VERSION 5.8 ;
BUSBITCHARS "[]" ;
DIVIDERCHAR "/" ;
UNITS
    DATABASE MICRONS 1000 ;
END UNITS

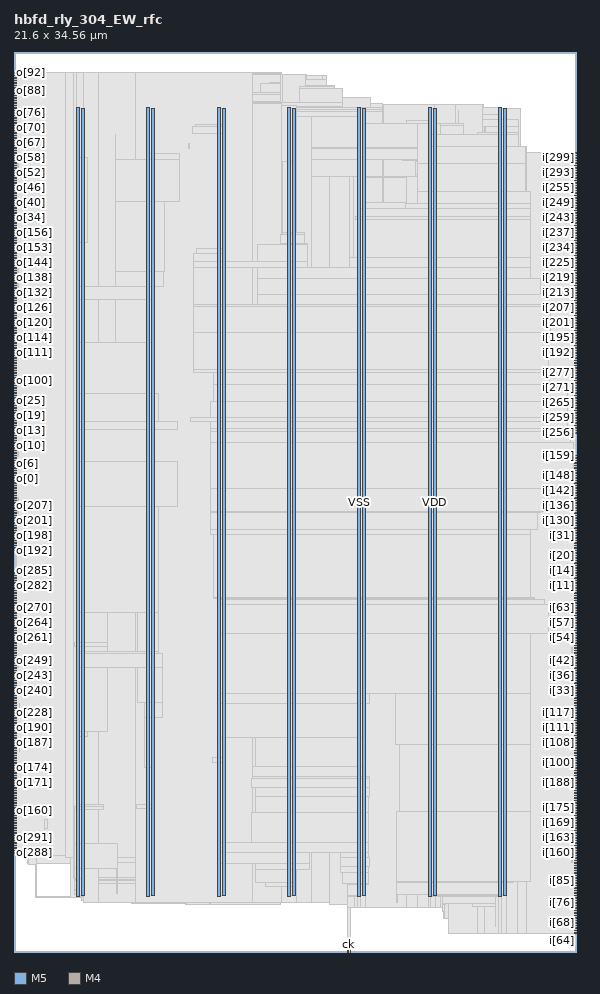
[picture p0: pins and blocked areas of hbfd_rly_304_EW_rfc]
MACRO hbfd_rly_304_EW_rfc
  FOREIGN hbfd_rly_304_EW_rfc 0 0 ;
  CLASS BLOCK ;
  SIZE 21.6 BY 34.56 ;
  PIN ck
    DIRECTION INPUT ;
    USE SIGNAL ;
    PORT
      LAYER M5 ;
        RECT  12.816 0 12.84 0.084 ;
    END
  END ck
  PIN i[0]
    DIRECTION INPUT ;
    USE SIGNAL ;
    PORT
      LAYER M4 ;
        RECT  21.516 13.008 21.6 13.032 ;
    END
  END i[0]
  PIN i[100]
    DIRECTION INPUT ;
    USE SIGNAL ;
    PORT
      LAYER M4 ;
        RECT  21.516 7.248 21.6 7.272 ;
    END
  END i[100]
  PIN i[101]
    DIRECTION INPUT ;
    USE SIGNAL ;
    PORT
      LAYER M4 ;
        RECT  21.516 7.344 21.6 7.368 ;
    END
  END i[101]
  PIN i[102]
    DIRECTION INPUT ;
    USE SIGNAL ;
    PORT
      LAYER M4 ;
        RECT  21.516 7.44 21.6 7.464 ;
    END
  END i[102]
  PIN i[103]
    DIRECTION INPUT ;
    USE SIGNAL ;
    PORT
      LAYER M4 ;
        RECT  21.516 7.536 21.6 7.56 ;
    END
  END i[103]
  PIN i[104]
    DIRECTION INPUT ;
    USE SIGNAL ;
    PORT
      LAYER M4 ;
        RECT  21.516 7.632 21.6 7.656 ;
    END
  END i[104]
  PIN i[105]
    DIRECTION INPUT ;
    USE SIGNAL ;
    PORT
      LAYER M4 ;
        RECT  21.516 7.728 21.6 7.752 ;
    END
  END i[105]
  PIN i[106]
    DIRECTION INPUT ;
    USE SIGNAL ;
    PORT
      LAYER M4 ;
        RECT  21.516 7.824 21.6 7.848 ;
    END
  END i[106]
  PIN i[107]
    DIRECTION INPUT ;
    USE SIGNAL ;
    PORT
      LAYER M4 ;
        RECT  21.516 7.92 21.6 7.944 ;
    END
  END i[107]
  PIN i[108]
    DIRECTION INPUT ;
    USE SIGNAL ;
    PORT
      LAYER M4 ;
        RECT  21.516 8.016 21.6 8.04 ;
    END
  END i[108]
  PIN i[109]
    DIRECTION INPUT ;
    USE SIGNAL ;
    PORT
      LAYER M4 ;
        RECT  21.516 8.112 21.6 8.136 ;
    END
  END i[109]
  PIN i[10]
    DIRECTION INPUT ;
    USE SIGNAL ;
    PORT
      LAYER M4 ;
        RECT  21.516 13.968 21.6 13.992 ;
    END
  END i[10]
  PIN i[110]
    DIRECTION INPUT ;
    USE SIGNAL ;
    PORT
      LAYER M4 ;
        RECT  21.516 8.208 21.6 8.232 ;
    END
  END i[110]
  PIN i[111]
    DIRECTION INPUT ;
    USE SIGNAL ;
    PORT
      LAYER M4 ;
        RECT  21.516 8.304 21.6 8.328 ;
    END
  END i[111]
  PIN i[112]
    DIRECTION INPUT ;
    USE SIGNAL ;
    PORT
      LAYER M4 ;
        RECT  21.516 8.4 21.6 8.424 ;
    END
  END i[112]
  PIN i[113]
    DIRECTION INPUT ;
    USE SIGNAL ;
    PORT
      LAYER M4 ;
        RECT  21.516 8.496 21.6 8.52 ;
    END
  END i[113]
  PIN i[114]
    DIRECTION INPUT ;
    USE SIGNAL ;
    PORT
      LAYER M4 ;
        RECT  21.516 8.592 21.6 8.616 ;
    END
  END i[114]
  PIN i[115]
    DIRECTION INPUT ;
    USE SIGNAL ;
    PORT
      LAYER M4 ;
        RECT  21.516 8.688 21.6 8.712 ;
    END
  END i[115]
  PIN i[116]
    DIRECTION INPUT ;
    USE SIGNAL ;
    PORT
      LAYER M4 ;
        RECT  21.516 8.784 21.6 8.808 ;
    END
  END i[116]
  PIN i[117]
    DIRECTION INPUT ;
    USE SIGNAL ;
    PORT
      LAYER M4 ;
        RECT  21.516 8.88 21.6 8.904 ;
    END
  END i[117]
  PIN i[118]
    DIRECTION INPUT ;
    USE SIGNAL ;
    PORT
      LAYER M4 ;
        RECT  21.516 8.976 21.6 9 ;
    END
  END i[118]
  PIN i[119]
    DIRECTION INPUT ;
    USE SIGNAL ;
    PORT
      LAYER M4 ;
        RECT  21.516 9.072 21.6 9.096 ;
    END
  END i[119]
  PIN i[11]
    DIRECTION INPUT ;
    USE SIGNAL ;
    PORT
      LAYER M4 ;
        RECT  21.516 14.064 21.6 14.088 ;
    END
  END i[11]
  PIN i[120]
    DIRECTION INPUT ;
    USE SIGNAL ;
    PORT
      LAYER M4 ;
        RECT  21.516 9.168 21.6 9.192 ;
    END
  END i[120]
  PIN i[121]
    DIRECTION INPUT ;
    USE SIGNAL ;
    PORT
      LAYER M4 ;
        RECT  21.516 9.264 21.6 9.288 ;
    END
  END i[121]
  PIN i[122]
    DIRECTION INPUT ;
    USE SIGNAL ;
    PORT
      LAYER M4 ;
        RECT  21.516 9.36 21.6 9.384 ;
    END
  END i[122]
  PIN i[123]
    DIRECTION INPUT ;
    USE SIGNAL ;
    PORT
      LAYER M4 ;
        RECT  21.516 9.456 21.6 9.48 ;
    END
  END i[123]
  PIN i[124]
    DIRECTION INPUT ;
    USE SIGNAL ;
    PORT
      LAYER M4 ;
        RECT  21.516 9.552 21.6 9.576 ;
    END
  END i[124]
  PIN i[125]
    DIRECTION INPUT ;
    USE SIGNAL ;
    PORT
      LAYER M4 ;
        RECT  21.516 9.648 21.6 9.672 ;
    END
  END i[125]
  PIN i[126]
    DIRECTION INPUT ;
    USE SIGNAL ;
    PORT
      LAYER M4 ;
        RECT  21.516 9.744 21.6 9.768 ;
    END
  END i[126]
  PIN i[127]
    DIRECTION INPUT ;
    USE SIGNAL ;
    PORT
      LAYER M4 ;
        RECT  21.516 9.84 21.6 9.864 ;
    END
  END i[127]
  PIN i[128]
    DIRECTION INPUT ;
    USE SIGNAL ;
    PORT
      LAYER M4 ;
        RECT  21.516 16.08 21.6 16.104 ;
    END
  END i[128]
  PIN i[129]
    DIRECTION INPUT ;
    USE SIGNAL ;
    PORT
      LAYER M4 ;
        RECT  21.516 16.176 21.6 16.2 ;
    END
  END i[129]
  PIN i[12]
    DIRECTION INPUT ;
    USE SIGNAL ;
    PORT
      LAYER M4 ;
        RECT  21.516 14.16 21.6 14.184 ;
    END
  END i[12]
  PIN i[130]
    DIRECTION INPUT ;
    USE SIGNAL ;
    PORT
      LAYER M4 ;
        RECT  21.516 16.272 21.6 16.296 ;
    END
  END i[130]
  PIN i[131]
    DIRECTION INPUT ;
    USE SIGNAL ;
    PORT
      LAYER M4 ;
        RECT  21.516 16.368 21.6 16.392 ;
    END
  END i[131]
  PIN i[132]
    DIRECTION INPUT ;
    USE SIGNAL ;
    PORT
      LAYER M4 ;
        RECT  21.516 16.464 21.6 16.488 ;
    END
  END i[132]
  PIN i[133]
    DIRECTION INPUT ;
    USE SIGNAL ;
    PORT
      LAYER M4 ;
        RECT  21.516 16.56 21.6 16.584 ;
    END
  END i[133]
  PIN i[134]
    DIRECTION INPUT ;
    USE SIGNAL ;
    PORT
      LAYER M4 ;
        RECT  21.516 16.656 21.6 16.68 ;
    END
  END i[134]
  PIN i[135]
    DIRECTION INPUT ;
    USE SIGNAL ;
    PORT
      LAYER M4 ;
        RECT  21.516 16.752 21.6 16.776 ;
    END
  END i[135]
  PIN i[136]
    DIRECTION INPUT ;
    USE SIGNAL ;
    PORT
      LAYER M4 ;
        RECT  21.516 16.848 21.6 16.872 ;
    END
  END i[136]
  PIN i[137]
    DIRECTION INPUT ;
    USE SIGNAL ;
    PORT
      LAYER M4 ;
        RECT  21.516 16.944 21.6 16.968 ;
    END
  END i[137]
  PIN i[138]
    DIRECTION INPUT ;
    USE SIGNAL ;
    PORT
      LAYER M4 ;
        RECT  21.516 17.04 21.6 17.064 ;
    END
  END i[138]
  PIN i[139]
    DIRECTION INPUT ;
    USE SIGNAL ;
    PORT
      LAYER M4 ;
        RECT  21.516 17.136 21.6 17.16 ;
    END
  END i[139]
  PIN i[13]
    DIRECTION INPUT ;
    USE SIGNAL ;
    PORT
      LAYER M4 ;
        RECT  21.516 14.256 21.6 14.28 ;
    END
  END i[13]
  PIN i[140]
    DIRECTION INPUT ;
    USE SIGNAL ;
    PORT
      LAYER M4 ;
        RECT  21.516 17.232 21.6 17.256 ;
    END
  END i[140]
  PIN i[141]
    DIRECTION INPUT ;
    USE SIGNAL ;
    PORT
      LAYER M4 ;
        RECT  21.516 17.328 21.6 17.352 ;
    END
  END i[141]
  PIN i[142]
    DIRECTION INPUT ;
    USE SIGNAL ;
    PORT
      LAYER M4 ;
        RECT  21.516 17.424 21.6 17.448 ;
    END
  END i[142]
  PIN i[143]
    DIRECTION INPUT ;
    USE SIGNAL ;
    PORT
      LAYER M4 ;
        RECT  21.516 17.52 21.6 17.544 ;
    END
  END i[143]
  PIN i[144]
    DIRECTION INPUT ;
    USE SIGNAL ;
    PORT
      LAYER M4 ;
        RECT  21.516 17.616 21.6 17.64 ;
    END
  END i[144]
  PIN i[145]
    DIRECTION INPUT ;
    USE SIGNAL ;
    PORT
      LAYER M4 ;
        RECT  21.516 17.712 21.6 17.736 ;
    END
  END i[145]
  PIN i[146]
    DIRECTION INPUT ;
    USE SIGNAL ;
    PORT
      LAYER M4 ;
        RECT  21.516 17.808 21.6 17.832 ;
    END
  END i[146]
  PIN i[147]
    DIRECTION INPUT ;
    USE SIGNAL ;
    PORT
      LAYER M4 ;
        RECT  21.516 17.904 21.6 17.928 ;
    END
  END i[147]
  PIN i[148]
    DIRECTION INPUT ;
    USE SIGNAL ;
    PORT
      LAYER M4 ;
        RECT  21.516 18 21.6 18.024 ;
    END
  END i[148]
  PIN i[149]
    DIRECTION INPUT ;
    USE SIGNAL ;
    PORT
      LAYER M4 ;
        RECT  21.516 18.096 21.6 18.12 ;
    END
  END i[149]
  PIN i[14]
    DIRECTION INPUT ;
    USE SIGNAL ;
    PORT
      LAYER M4 ;
        RECT  21.516 14.352 21.6 14.376 ;
    END
  END i[14]
  PIN i[150]
    DIRECTION INPUT ;
    USE SIGNAL ;
    PORT
      LAYER M4 ;
        RECT  21.516 18.192 21.6 18.216 ;
    END
  END i[150]
  PIN i[151]
    DIRECTION INPUT ;
    USE SIGNAL ;
    PORT
      LAYER M4 ;
        RECT  21.516 18.288 21.6 18.312 ;
    END
  END i[151]
  PIN i[152]
    DIRECTION INPUT ;
    USE SIGNAL ;
    PORT
      LAYER M4 ;
        RECT  21.516 18.384 21.6 18.408 ;
    END
  END i[152]
  PIN i[153]
    DIRECTION INPUT ;
    USE SIGNAL ;
    PORT
      LAYER M4 ;
        RECT  21.516 18.48 21.6 18.504 ;
    END
  END i[153]
  PIN i[154]
    DIRECTION INPUT ;
    USE SIGNAL ;
    PORT
      LAYER M4 ;
        RECT  21.516 18.576 21.6 18.6 ;
    END
  END i[154]
  PIN i[155]
    DIRECTION INPUT ;
    USE SIGNAL ;
    PORT
      LAYER M4 ;
        RECT  21.516 18.672 21.6 18.696 ;
    END
  END i[155]
  PIN i[156]
    DIRECTION INPUT ;
    USE SIGNAL ;
    PORT
      LAYER M4 ;
        RECT  21.516 18.768 21.6 18.792 ;
    END
  END i[156]
  PIN i[157]
    DIRECTION INPUT ;
    USE SIGNAL ;
    PORT
      LAYER M4 ;
        RECT  21.516 18.864 21.6 18.888 ;
    END
  END i[157]
  PIN i[158]
    DIRECTION INPUT ;
    USE SIGNAL ;
    PORT
      LAYER M4 ;
        RECT  21.516 18.96 21.6 18.984 ;
    END
  END i[158]
  PIN i[159]
    DIRECTION INPUT ;
    USE SIGNAL ;
    PORT
      LAYER M4 ;
        RECT  21.516 19.056 21.6 19.08 ;
    END
  END i[159]
  PIN i[15]
    DIRECTION INPUT ;
    USE SIGNAL ;
    PORT
      LAYER M4 ;
        RECT  21.516 14.448 21.6 14.472 ;
    END
  END i[15]
  PIN i[160]
    DIRECTION INPUT ;
    USE SIGNAL ;
    PORT
      LAYER M4 ;
        RECT  21.516 3.792 21.6 3.816 ;
    END
  END i[160]
  PIN i[161]
    DIRECTION INPUT ;
    USE SIGNAL ;
    PORT
      LAYER M4 ;
        RECT  21.516 3.888 21.6 3.912 ;
    END
  END i[161]
  PIN i[162]
    DIRECTION INPUT ;
    USE SIGNAL ;
    PORT
      LAYER M4 ;
        RECT  21.516 3.984 21.6 4.008 ;
    END
  END i[162]
  PIN i[163]
    DIRECTION INPUT ;
    USE SIGNAL ;
    PORT
      LAYER M4 ;
        RECT  21.516 4.08 21.6 4.104 ;
    END
  END i[163]
  PIN i[164]
    DIRECTION INPUT ;
    USE SIGNAL ;
    PORT
      LAYER M4 ;
        RECT  21.516 4.176 21.6 4.2 ;
    END
  END i[164]
  PIN i[165]
    DIRECTION INPUT ;
    USE SIGNAL ;
    PORT
      LAYER M4 ;
        RECT  21.516 4.272 21.6 4.296 ;
    END
  END i[165]
  PIN i[166]
    DIRECTION INPUT ;
    USE SIGNAL ;
    PORT
      LAYER M4 ;
        RECT  21.516 4.368 21.6 4.392 ;
    END
  END i[166]
  PIN i[167]
    DIRECTION INPUT ;
    USE SIGNAL ;
    PORT
      LAYER M4 ;
        RECT  21.516 4.464 21.6 4.488 ;
    END
  END i[167]
  PIN i[168]
    DIRECTION INPUT ;
    USE SIGNAL ;
    PORT
      LAYER M4 ;
        RECT  21.516 4.56 21.6 4.584 ;
    END
  END i[168]
  PIN i[169]
    DIRECTION INPUT ;
    USE SIGNAL ;
    PORT
      LAYER M4 ;
        RECT  21.516 4.656 21.6 4.68 ;
    END
  END i[169]
  PIN i[16]
    DIRECTION INPUT ;
    USE SIGNAL ;
    PORT
      LAYER M4 ;
        RECT  21.516 14.544 21.6 14.568 ;
    END
  END i[16]
  PIN i[170]
    DIRECTION INPUT ;
    USE SIGNAL ;
    PORT
      LAYER M4 ;
        RECT  21.516 4.752 21.6 4.776 ;
    END
  END i[170]
  PIN i[171]
    DIRECTION INPUT ;
    USE SIGNAL ;
    PORT
      LAYER M4 ;
        RECT  21.516 4.848 21.6 4.872 ;
    END
  END i[171]
  PIN i[172]
    DIRECTION INPUT ;
    USE SIGNAL ;
    PORT
      LAYER M4 ;
        RECT  21.516 4.944 21.6 4.968 ;
    END
  END i[172]
  PIN i[173]
    DIRECTION INPUT ;
    USE SIGNAL ;
    PORT
      LAYER M4 ;
        RECT  21.516 5.04 21.6 5.064 ;
    END
  END i[173]
  PIN i[174]
    DIRECTION INPUT ;
    USE SIGNAL ;
    PORT
      LAYER M4 ;
        RECT  21.516 5.136 21.6 5.16 ;
    END
  END i[174]
  PIN i[175]
    DIRECTION INPUT ;
    USE SIGNAL ;
    PORT
      LAYER M4 ;
        RECT  21.516 5.232 21.6 5.256 ;
    END
  END i[175]
  PIN i[176]
    DIRECTION INPUT ;
    USE SIGNAL ;
    PORT
      LAYER M4 ;
        RECT  21.516 5.328 21.6 5.352 ;
    END
  END i[176]
  PIN i[177]
    DIRECTION INPUT ;
    USE SIGNAL ;
    PORT
      LAYER M4 ;
        RECT  21.516 5.424 21.6 5.448 ;
    END
  END i[177]
  PIN i[178]
    DIRECTION INPUT ;
    USE SIGNAL ;
    PORT
      LAYER M4 ;
        RECT  21.516 5.52 21.6 5.544 ;
    END
  END i[178]
  PIN i[179]
    DIRECTION INPUT ;
    USE SIGNAL ;
    PORT
      LAYER M4 ;
        RECT  21.516 5.616 21.6 5.64 ;
    END
  END i[179]
  PIN i[17]
    DIRECTION INPUT ;
    USE SIGNAL ;
    PORT
      LAYER M4 ;
        RECT  21.516 14.64 21.6 14.664 ;
    END
  END i[17]
  PIN i[180]
    DIRECTION INPUT ;
    USE SIGNAL ;
    PORT
      LAYER M4 ;
        RECT  21.516 5.712 21.6 5.736 ;
    END
  END i[180]
  PIN i[181]
    DIRECTION INPUT ;
    USE SIGNAL ;
    PORT
      LAYER M4 ;
        RECT  21.516 5.808 21.6 5.832 ;
    END
  END i[181]
  PIN i[182]
    DIRECTION INPUT ;
    USE SIGNAL ;
    PORT
      LAYER M4 ;
        RECT  21.516 5.904 21.6 5.928 ;
    END
  END i[182]
  PIN i[183]
    DIRECTION INPUT ;
    USE SIGNAL ;
    PORT
      LAYER M4 ;
        RECT  21.516 6 21.6 6.024 ;
    END
  END i[183]
  PIN i[184]
    DIRECTION INPUT ;
    USE SIGNAL ;
    PORT
      LAYER M4 ;
        RECT  21.516 6.096 21.6 6.12 ;
    END
  END i[184]
  PIN i[185]
    DIRECTION INPUT ;
    USE SIGNAL ;
    PORT
      LAYER M4 ;
        RECT  21.516 6.192 21.6 6.216 ;
    END
  END i[185]
  PIN i[186]
    DIRECTION INPUT ;
    USE SIGNAL ;
    PORT
      LAYER M4 ;
        RECT  21.516 6.288 21.6 6.312 ;
    END
  END i[186]
  PIN i[187]
    DIRECTION INPUT ;
    USE SIGNAL ;
    PORT
      LAYER M4 ;
        RECT  21.516 6.384 21.6 6.408 ;
    END
  END i[187]
  PIN i[188]
    DIRECTION INPUT ;
    USE SIGNAL ;
    PORT
      LAYER M4 ;
        RECT  21.516 6.48 21.6 6.504 ;
    END
  END i[188]
  PIN i[189]
    DIRECTION INPUT ;
    USE SIGNAL ;
    PORT
      LAYER M4 ;
        RECT  21.516 6.576 21.6 6.6 ;
    END
  END i[189]
  PIN i[18]
    DIRECTION INPUT ;
    USE SIGNAL ;
    PORT
      LAYER M4 ;
        RECT  21.516 14.736 21.6 14.76 ;
    END
  END i[18]
  PIN i[190]
    DIRECTION INPUT ;
    USE SIGNAL ;
    PORT
      LAYER M4 ;
        RECT  21.516 6.672 21.6 6.696 ;
    END
  END i[190]
  PIN i[191]
    DIRECTION INPUT ;
    USE SIGNAL ;
    PORT
      LAYER M4 ;
        RECT  21.516 6.768 21.6 6.792 ;
    END
  END i[191]
  PIN i[192]
    DIRECTION INPUT ;
    USE SIGNAL ;
    PORT
      LAYER M4 ;
        RECT  21.516 22.992 21.6 23.016 ;
    END
  END i[192]
  PIN i[193]
    DIRECTION INPUT ;
    USE SIGNAL ;
    PORT
      LAYER M4 ;
        RECT  21.516 23.088 21.6 23.112 ;
    END
  END i[193]
  PIN i[194]
    DIRECTION INPUT ;
    USE SIGNAL ;
    PORT
      LAYER M4 ;
        RECT  21.516 23.184 21.6 23.208 ;
    END
  END i[194]
  PIN i[195]
    DIRECTION INPUT ;
    USE SIGNAL ;
    PORT
      LAYER M4 ;
        RECT  21.516 23.28 21.6 23.304 ;
    END
  END i[195]
  PIN i[196]
    DIRECTION INPUT ;
    USE SIGNAL ;
    PORT
      LAYER M4 ;
        RECT  21.516 23.376 21.6 23.4 ;
    END
  END i[196]
  PIN i[197]
    DIRECTION INPUT ;
    USE SIGNAL ;
    PORT
      LAYER M4 ;
        RECT  21.516 23.472 21.6 23.496 ;
    END
  END i[197]
  PIN i[198]
    DIRECTION INPUT ;
    USE SIGNAL ;
    PORT
      LAYER M4 ;
        RECT  21.516 23.568 21.6 23.592 ;
    END
  END i[198]
  PIN i[199]
    DIRECTION INPUT ;
    USE SIGNAL ;
    PORT
      LAYER M4 ;
        RECT  21.516 23.664 21.6 23.688 ;
    END
  END i[199]
  PIN i[19]
    DIRECTION INPUT ;
    USE SIGNAL ;
    PORT
      LAYER M4 ;
        RECT  21.516 14.832 21.6 14.856 ;
    END
  END i[19]
  PIN i[1]
    DIRECTION INPUT ;
    USE SIGNAL ;
    PORT
      LAYER M4 ;
        RECT  21.516 13.104 21.6 13.128 ;
    END
  END i[1]
  PIN i[200]
    DIRECTION INPUT ;
    USE SIGNAL ;
    PORT
      LAYER M4 ;
        RECT  21.516 23.76 21.6 23.784 ;
    END
  END i[200]
  PIN i[201]
    DIRECTION INPUT ;
    USE SIGNAL ;
    PORT
      LAYER M4 ;
        RECT  21.516 23.856 21.6 23.88 ;
    END
  END i[201]
  PIN i[202]
    DIRECTION INPUT ;
    USE SIGNAL ;
    PORT
      LAYER M4 ;
        RECT  21.516 23.952 21.6 23.976 ;
    END
  END i[202]
  PIN i[203]
    DIRECTION INPUT ;
    USE SIGNAL ;
    PORT
      LAYER M4 ;
        RECT  21.516 24.048 21.6 24.072 ;
    END
  END i[203]
  PIN i[204]
    DIRECTION INPUT ;
    USE SIGNAL ;
    PORT
      LAYER M4 ;
        RECT  21.516 24.144 21.6 24.168 ;
    END
  END i[204]
  PIN i[205]
    DIRECTION INPUT ;
    USE SIGNAL ;
    PORT
      LAYER M4 ;
        RECT  21.516 24.24 21.6 24.264 ;
    END
  END i[205]
  PIN i[206]
    DIRECTION INPUT ;
    USE SIGNAL ;
    PORT
      LAYER M4 ;
        RECT  21.516 24.336 21.6 24.36 ;
    END
  END i[206]
  PIN i[207]
    DIRECTION INPUT ;
    USE SIGNAL ;
    PORT
      LAYER M4 ;
        RECT  21.516 24.432 21.6 24.456 ;
    END
  END i[207]
  PIN i[208]
    DIRECTION INPUT ;
    USE SIGNAL ;
    PORT
      LAYER M4 ;
        RECT  21.516 24.528 21.6 24.552 ;
    END
  END i[208]
  PIN i[209]
    DIRECTION INPUT ;
    USE SIGNAL ;
    PORT
      LAYER M4 ;
        RECT  21.516 24.624 21.6 24.648 ;
    END
  END i[209]
  PIN i[20]
    DIRECTION INPUT ;
    USE SIGNAL ;
    PORT
      LAYER M4 ;
        RECT  21.516 14.928 21.6 14.952 ;
    END
  END i[20]
  PIN i[210]
    DIRECTION INPUT ;
    USE SIGNAL ;
    PORT
      LAYER M4 ;
        RECT  21.516 24.72 21.6 24.744 ;
    END
  END i[210]
  PIN i[211]
    DIRECTION INPUT ;
    USE SIGNAL ;
    PORT
      LAYER M4 ;
        RECT  21.516 24.816 21.6 24.84 ;
    END
  END i[211]
  PIN i[212]
    DIRECTION INPUT ;
    USE SIGNAL ;
    PORT
      LAYER M4 ;
        RECT  21.516 24.912 21.6 24.936 ;
    END
  END i[212]
  PIN i[213]
    DIRECTION INPUT ;
    USE SIGNAL ;
    PORT
      LAYER M4 ;
        RECT  21.516 25.008 21.6 25.032 ;
    END
  END i[213]
  PIN i[214]
    DIRECTION INPUT ;
    USE SIGNAL ;
    PORT
      LAYER M4 ;
        RECT  21.516 25.104 21.6 25.128 ;
    END
  END i[214]
  PIN i[215]
    DIRECTION INPUT ;
    USE SIGNAL ;
    PORT
      LAYER M4 ;
        RECT  21.516 25.2 21.6 25.224 ;
    END
  END i[215]
  PIN i[216]
    DIRECTION INPUT ;
    USE SIGNAL ;
    PORT
      LAYER M4 ;
        RECT  21.516 25.296 21.6 25.32 ;
    END
  END i[216]
  PIN i[217]
    DIRECTION INPUT ;
    USE SIGNAL ;
    PORT
      LAYER M4 ;
        RECT  21.516 25.392 21.6 25.416 ;
    END
  END i[217]
  PIN i[218]
    DIRECTION INPUT ;
    USE SIGNAL ;
    PORT
      LAYER M4 ;
        RECT  21.516 25.488 21.6 25.512 ;
    END
  END i[218]
  PIN i[219]
    DIRECTION INPUT ;
    USE SIGNAL ;
    PORT
      LAYER M4 ;
        RECT  21.516 25.584 21.6 25.608 ;
    END
  END i[219]
  PIN i[21]
    DIRECTION INPUT ;
    USE SIGNAL ;
    PORT
      LAYER M4 ;
        RECT  21.516 15.024 21.6 15.048 ;
    END
  END i[21]
  PIN i[220]
    DIRECTION INPUT ;
    USE SIGNAL ;
    PORT
      LAYER M4 ;
        RECT  21.516 25.68 21.6 25.704 ;
    END
  END i[220]
  PIN i[221]
    DIRECTION INPUT ;
    USE SIGNAL ;
    PORT
      LAYER M4 ;
        RECT  21.516 25.776 21.6 25.8 ;
    END
  END i[221]
  PIN i[222]
    DIRECTION INPUT ;
    USE SIGNAL ;
    PORT
      LAYER M4 ;
        RECT  21.516 25.872 21.6 25.896 ;
    END
  END i[222]
  PIN i[223]
    DIRECTION INPUT ;
    USE SIGNAL ;
    PORT
      LAYER M4 ;
        RECT  21.516 25.968 21.6 25.992 ;
    END
  END i[223]
  PIN i[224]
    DIRECTION INPUT ;
    USE SIGNAL ;
    PORT
      LAYER M4 ;
        RECT  21.516 26.064 21.6 26.088 ;
    END
  END i[224]
  PIN i[225]
    DIRECTION INPUT ;
    USE SIGNAL ;
    PORT
      LAYER M4 ;
        RECT  21.516 26.16 21.6 26.184 ;
    END
  END i[225]
  PIN i[226]
    DIRECTION INPUT ;
    USE SIGNAL ;
    PORT
      LAYER M4 ;
        RECT  21.516 26.256 21.6 26.28 ;
    END
  END i[226]
  PIN i[227]
    DIRECTION INPUT ;
    USE SIGNAL ;
    PORT
      LAYER M4 ;
        RECT  21.516 26.352 21.6 26.376 ;
    END
  END i[227]
  PIN i[228]
    DIRECTION INPUT ;
    USE SIGNAL ;
    PORT
      LAYER M4 ;
        RECT  21.516 26.448 21.6 26.472 ;
    END
  END i[228]
  PIN i[229]
    DIRECTION INPUT ;
    USE SIGNAL ;
    PORT
      LAYER M4 ;
        RECT  21.516 26.544 21.6 26.568 ;
    END
  END i[229]
  PIN i[22]
    DIRECTION INPUT ;
    USE SIGNAL ;
    PORT
      LAYER M4 ;
        RECT  21.516 15.12 21.6 15.144 ;
    END
  END i[22]
  PIN i[230]
    DIRECTION INPUT ;
    USE SIGNAL ;
    PORT
      LAYER M4 ;
        RECT  21.516 26.64 21.6 26.664 ;
    END
  END i[230]
  PIN i[231]
    DIRECTION INPUT ;
    USE SIGNAL ;
    PORT
      LAYER M4 ;
        RECT  21.516 26.736 21.6 26.76 ;
    END
  END i[231]
  PIN i[232]
    DIRECTION INPUT ;
    USE SIGNAL ;
    PORT
      LAYER M4 ;
        RECT  21.516 26.832 21.6 26.856 ;
    END
  END i[232]
  PIN i[233]
    DIRECTION INPUT ;
    USE SIGNAL ;
    PORT
      LAYER M4 ;
        RECT  21.516 26.928 21.6 26.952 ;
    END
  END i[233]
  PIN i[234]
    DIRECTION INPUT ;
    USE SIGNAL ;
    PORT
      LAYER M4 ;
        RECT  21.516 27.024 21.6 27.048 ;
    END
  END i[234]
  PIN i[235]
    DIRECTION INPUT ;
    USE SIGNAL ;
    PORT
      LAYER M4 ;
        RECT  21.516 27.12 21.6 27.144 ;
    END
  END i[235]
  PIN i[236]
    DIRECTION INPUT ;
    USE SIGNAL ;
    PORT
      LAYER M4 ;
        RECT  21.516 27.216 21.6 27.24 ;
    END
  END i[236]
  PIN i[237]
    DIRECTION INPUT ;
    USE SIGNAL ;
    PORT
      LAYER M4 ;
        RECT  21.516 27.312 21.6 27.336 ;
    END
  END i[237]
  PIN i[238]
    DIRECTION INPUT ;
    USE SIGNAL ;
    PORT
      LAYER M4 ;
        RECT  21.516 27.408 21.6 27.432 ;
    END
  END i[238]
  PIN i[239]
    DIRECTION INPUT ;
    USE SIGNAL ;
    PORT
      LAYER M4 ;
        RECT  21.516 27.504 21.6 27.528 ;
    END
  END i[239]
  PIN i[23]
    DIRECTION INPUT ;
    USE SIGNAL ;
    PORT
      LAYER M4 ;
        RECT  21.516 15.216 21.6 15.24 ;
    END
  END i[23]
  PIN i[240]
    DIRECTION INPUT ;
    USE SIGNAL ;
    PORT
      LAYER M4 ;
        RECT  21.516 27.6 21.6 27.624 ;
    END
  END i[240]
  PIN i[241]
    DIRECTION INPUT ;
    USE SIGNAL ;
    PORT
      LAYER M4 ;
        RECT  21.516 27.696 21.6 27.72 ;
    END
  END i[241]
  PIN i[242]
    DIRECTION INPUT ;
    USE SIGNAL ;
    PORT
      LAYER M4 ;
        RECT  21.516 27.792 21.6 27.816 ;
    END
  END i[242]
  PIN i[243]
    DIRECTION INPUT ;
    USE SIGNAL ;
    PORT
      LAYER M4 ;
        RECT  21.516 27.888 21.6 27.912 ;
    END
  END i[243]
  PIN i[244]
    DIRECTION INPUT ;
    USE SIGNAL ;
    PORT
      LAYER M4 ;
        RECT  21.516 27.984 21.6 28.008 ;
    END
  END i[244]
  PIN i[245]
    DIRECTION INPUT ;
    USE SIGNAL ;
    PORT
      LAYER M4 ;
        RECT  21.516 28.08 21.6 28.104 ;
    END
  END i[245]
  PIN i[246]
    DIRECTION INPUT ;
    USE SIGNAL ;
    PORT
      LAYER M4 ;
        RECT  21.516 28.176 21.6 28.2 ;
    END
  END i[246]
  PIN i[247]
    DIRECTION INPUT ;
    USE SIGNAL ;
    PORT
      LAYER M4 ;
        RECT  21.516 28.272 21.6 28.296 ;
    END
  END i[247]
  PIN i[248]
    DIRECTION INPUT ;
    USE SIGNAL ;
    PORT
      LAYER M4 ;
        RECT  21.516 28.368 21.6 28.392 ;
    END
  END i[248]
  PIN i[249]
    DIRECTION INPUT ;
    USE SIGNAL ;
    PORT
      LAYER M4 ;
        RECT  21.516 28.464 21.6 28.488 ;
    END
  END i[249]
  PIN i[24]
    DIRECTION INPUT ;
    USE SIGNAL ;
    PORT
      LAYER M4 ;
        RECT  21.516 15.312 21.6 15.336 ;
    END
  END i[24]
  PIN i[250]
    DIRECTION INPUT ;
    USE SIGNAL ;
    PORT
      LAYER M4 ;
        RECT  21.516 28.56 21.6 28.584 ;
    END
  END i[250]
  PIN i[251]
    DIRECTION INPUT ;
    USE SIGNAL ;
    PORT
      LAYER M4 ;
        RECT  21.516 28.656 21.6 28.68 ;
    END
  END i[251]
  PIN i[252]
    DIRECTION INPUT ;
    USE SIGNAL ;
    PORT
      LAYER M4 ;
        RECT  21.516 28.752 21.6 28.776 ;
    END
  END i[252]
  PIN i[253]
    DIRECTION INPUT ;
    USE SIGNAL ;
    PORT
      LAYER M4 ;
        RECT  21.516 28.848 21.6 28.872 ;
    END
  END i[253]
  PIN i[254]
    DIRECTION INPUT ;
    USE SIGNAL ;
    PORT
      LAYER M4 ;
        RECT  21.516 28.944 21.6 28.968 ;
    END
  END i[254]
  PIN i[255]
    DIRECTION INPUT ;
    USE SIGNAL ;
    PORT
      LAYER M4 ;
        RECT  21.516 29.04 21.6 29.064 ;
    END
  END i[255]
  PIN i[256]
    DIRECTION INPUT ;
    USE SIGNAL ;
    PORT
      LAYER M4 ;
        RECT  21.516 19.92 21.6 19.944 ;
    END
  END i[256]
  PIN i[257]
    DIRECTION INPUT ;
    USE SIGNAL ;
    PORT
      LAYER M4 ;
        RECT  21.516 20.016 21.6 20.04 ;
    END
  END i[257]
  PIN i[258]
    DIRECTION INPUT ;
    USE SIGNAL ;
    PORT
      LAYER M4 ;
        RECT  21.516 20.112 21.6 20.136 ;
    END
  END i[258]
  PIN i[259]
    DIRECTION INPUT ;
    USE SIGNAL ;
    PORT
      LAYER M4 ;
        RECT  21.516 20.208 21.6 20.232 ;
    END
  END i[259]
  PIN i[25]
    DIRECTION INPUT ;
    USE SIGNAL ;
    PORT
      LAYER M4 ;
        RECT  21.516 15.408 21.6 15.432 ;
    END
  END i[25]
  PIN i[260]
    DIRECTION INPUT ;
    USE SIGNAL ;
    PORT
      LAYER M4 ;
        RECT  21.516 20.304 21.6 20.328 ;
    END
  END i[260]
  PIN i[261]
    DIRECTION INPUT ;
    USE SIGNAL ;
    PORT
      LAYER M4 ;
        RECT  21.516 20.4 21.6 20.424 ;
    END
  END i[261]
  PIN i[262]
    DIRECTION INPUT ;
    USE SIGNAL ;
    PORT
      LAYER M4 ;
        RECT  21.516 20.496 21.6 20.52 ;
    END
  END i[262]
  PIN i[263]
    DIRECTION INPUT ;
    USE SIGNAL ;
    PORT
      LAYER M4 ;
        RECT  21.516 20.592 21.6 20.616 ;
    END
  END i[263]
  PIN i[264]
    DIRECTION INPUT ;
    USE SIGNAL ;
    PORT
      LAYER M4 ;
        RECT  21.516 20.688 21.6 20.712 ;
    END
  END i[264]
  PIN i[265]
    DIRECTION INPUT ;
    USE SIGNAL ;
    PORT
      LAYER M4 ;
        RECT  21.516 20.784 21.6 20.808 ;
    END
  END i[265]
  PIN i[266]
    DIRECTION INPUT ;
    USE SIGNAL ;
    PORT
      LAYER M4 ;
        RECT  21.516 20.88 21.6 20.904 ;
    END
  END i[266]
  PIN i[267]
    DIRECTION INPUT ;
    USE SIGNAL ;
    PORT
      LAYER M4 ;
        RECT  21.516 20.976 21.6 21 ;
    END
  END i[267]
  PIN i[268]
    DIRECTION INPUT ;
    USE SIGNAL ;
    PORT
      LAYER M4 ;
        RECT  21.516 21.072 21.6 21.096 ;
    END
  END i[268]
  PIN i[269]
    DIRECTION INPUT ;
    USE SIGNAL ;
    PORT
      LAYER M4 ;
        RECT  21.516 21.168 21.6 21.192 ;
    END
  END i[269]
  PIN i[26]
    DIRECTION INPUT ;
    USE SIGNAL ;
    PORT
      LAYER M4 ;
        RECT  21.516 15.504 21.6 15.528 ;
    END
  END i[26]
  PIN i[270]
    DIRECTION INPUT ;
    USE SIGNAL ;
    PORT
      LAYER M4 ;
        RECT  21.516 21.264 21.6 21.288 ;
    END
  END i[270]
  PIN i[271]
    DIRECTION INPUT ;
    USE SIGNAL ;
    PORT
      LAYER M4 ;
        RECT  21.516 21.36 21.6 21.384 ;
    END
  END i[271]
  PIN i[272]
    DIRECTION INPUT ;
    USE SIGNAL ;
    PORT
      LAYER M4 ;
        RECT  21.516 21.456 21.6 21.48 ;
    END
  END i[272]
  PIN i[273]
    DIRECTION INPUT ;
    USE SIGNAL ;
    PORT
      LAYER M4 ;
        RECT  21.516 21.552 21.6 21.576 ;
    END
  END i[273]
  PIN i[274]
    DIRECTION INPUT ;
    USE SIGNAL ;
    PORT
      LAYER M4 ;
        RECT  21.516 21.648 21.6 21.672 ;
    END
  END i[274]
  PIN i[275]
    DIRECTION INPUT ;
    USE SIGNAL ;
    PORT
      LAYER M4 ;
        RECT  21.516 21.744 21.6 21.768 ;
    END
  END i[275]
  PIN i[276]
    DIRECTION INPUT ;
    USE SIGNAL ;
    PORT
      LAYER M4 ;
        RECT  21.516 21.84 21.6 21.864 ;
    END
  END i[276]
  PIN i[277]
    DIRECTION INPUT ;
    USE SIGNAL ;
    PORT
      LAYER M4 ;
        RECT  21.516 21.936 21.6 21.96 ;
    END
  END i[277]
  PIN i[278]
    DIRECTION INPUT ;
    USE SIGNAL ;
    PORT
      LAYER M4 ;
        RECT  21.516 22.032 21.6 22.056 ;
    END
  END i[278]
  PIN i[279]
    DIRECTION INPUT ;
    USE SIGNAL ;
    PORT
      LAYER M4 ;
        RECT  21.516 22.128 21.6 22.152 ;
    END
  END i[279]
  PIN i[27]
    DIRECTION INPUT ;
    USE SIGNAL ;
    PORT
      LAYER M4 ;
        RECT  21.516 15.6 21.6 15.624 ;
    END
  END i[27]
  PIN i[280]
    DIRECTION INPUT ;
    USE SIGNAL ;
    PORT
      LAYER M4 ;
        RECT  21.516 22.224 21.6 22.248 ;
    END
  END i[280]
  PIN i[281]
    DIRECTION INPUT ;
    USE SIGNAL ;
    PORT
      LAYER M4 ;
        RECT  21.516 22.32 21.6 22.344 ;
    END
  END i[281]
  PIN i[282]
    DIRECTION INPUT ;
    USE SIGNAL ;
    PORT
      LAYER M4 ;
        RECT  21.516 22.416 21.6 22.44 ;
    END
  END i[282]
  PIN i[283]
    DIRECTION INPUT ;
    USE SIGNAL ;
    PORT
      LAYER M4 ;
        RECT  21.516 22.512 21.6 22.536 ;
    END
  END i[283]
  PIN i[284]
    DIRECTION INPUT ;
    USE SIGNAL ;
    PORT
      LAYER M4 ;
        RECT  21.516 22.608 21.6 22.632 ;
    END
  END i[284]
  PIN i[285]
    DIRECTION INPUT ;
    USE SIGNAL ;
    PORT
      LAYER M4 ;
        RECT  21.516 22.704 21.6 22.728 ;
    END
  END i[285]
  PIN i[286]
    DIRECTION INPUT ;
    USE SIGNAL ;
    PORT
      LAYER M4 ;
        RECT  21.516 22.8 21.6 22.824 ;
    END
  END i[286]
  PIN i[287]
    DIRECTION INPUT ;
    USE SIGNAL ;
    PORT
      LAYER M4 ;
        RECT  21.516 22.896 21.6 22.92 ;
    END
  END i[287]
  PIN i[288]
    DIRECTION INPUT ;
    USE SIGNAL ;
    PORT
      LAYER M4 ;
        RECT  21.516 29.136 21.6 29.16 ;
    END
  END i[288]
  PIN i[289]
    DIRECTION INPUT ;
    USE SIGNAL ;
    PORT
      LAYER M4 ;
        RECT  21.516 29.232 21.6 29.256 ;
    END
  END i[289]
  PIN i[28]
    DIRECTION INPUT ;
    USE SIGNAL ;
    PORT
      LAYER M4 ;
        RECT  21.516 15.696 21.6 15.72 ;
    END
  END i[28]
  PIN i[290]
    DIRECTION INPUT ;
    USE SIGNAL ;
    PORT
      LAYER M4 ;
        RECT  21.516 29.328 21.6 29.352 ;
    END
  END i[290]
  PIN i[291]
    DIRECTION INPUT ;
    USE SIGNAL ;
    PORT
      LAYER M4 ;
        RECT  21.516 29.424 21.6 29.448 ;
    END
  END i[291]
  PIN i[292]
    DIRECTION INPUT ;
    USE SIGNAL ;
    PORT
      LAYER M4 ;
        RECT  21.516 29.52 21.6 29.544 ;
    END
  END i[292]
  PIN i[293]
    DIRECTION INPUT ;
    USE SIGNAL ;
    PORT
      LAYER M4 ;
        RECT  21.516 29.616 21.6 29.64 ;
    END
  END i[293]
  PIN i[294]
    DIRECTION INPUT ;
    USE SIGNAL ;
    PORT
      LAYER M4 ;
        RECT  21.516 29.712 21.6 29.736 ;
    END
  END i[294]
  PIN i[295]
    DIRECTION INPUT ;
    USE SIGNAL ;
    PORT
      LAYER M4 ;
        RECT  21.516 29.808 21.6 29.832 ;
    END
  END i[295]
  PIN i[296]
    DIRECTION INPUT ;
    USE SIGNAL ;
    PORT
      LAYER M4 ;
        RECT  21.516 29.904 21.6 29.928 ;
    END
  END i[296]
  PIN i[297]
    DIRECTION INPUT ;
    USE SIGNAL ;
    PORT
      LAYER M4 ;
        RECT  21.516 30 21.6 30.024 ;
    END
  END i[297]
  PIN i[298]
    DIRECTION INPUT ;
    USE SIGNAL ;
    PORT
      LAYER M4 ;
        RECT  21.516 30.096 21.6 30.12 ;
    END
  END i[298]
  PIN i[299]
    DIRECTION INPUT ;
    USE SIGNAL ;
    PORT
      LAYER M4 ;
        RECT  21.516 30.192 21.6 30.216 ;
    END
  END i[299]
  PIN i[29]
    DIRECTION INPUT ;
    USE SIGNAL ;
    PORT
      LAYER M4 ;
        RECT  21.516 15.792 21.6 15.816 ;
    END
  END i[29]
  PIN i[2]
    DIRECTION INPUT ;
    USE SIGNAL ;
    PORT
      LAYER M4 ;
        RECT  21.516 13.2 21.6 13.224 ;
    END
  END i[2]
  PIN i[300]
    DIRECTION INPUT ;
    USE SIGNAL ;
    PORT
      LAYER M4 ;
        RECT  21.516 30.288 21.6 30.312 ;
    END
  END i[300]
  PIN i[301]
    DIRECTION INPUT ;
    USE SIGNAL ;
    PORT
      LAYER M4 ;
        RECT  21.516 30.384 21.6 30.408 ;
    END
  END i[301]
  PIN i[302]
    DIRECTION INPUT ;
    USE SIGNAL ;
    PORT
      LAYER M4 ;
        RECT  21.516 30.48 21.6 30.504 ;
    END
  END i[302]
  PIN i[303]
    DIRECTION INPUT ;
    USE SIGNAL ;
    PORT
      LAYER M4 ;
        RECT  21.516 30.576 21.6 30.6 ;
    END
  END i[303]
  PIN i[30]
    DIRECTION INPUT ;
    USE SIGNAL ;
    PORT
      LAYER M4 ;
        RECT  21.516 15.888 21.6 15.912 ;
    END
  END i[30]
  PIN i[31]
    DIRECTION INPUT ;
    USE SIGNAL ;
    PORT
      LAYER M4 ;
        RECT  21.516 15.984 21.6 16.008 ;
    END
  END i[31]
  PIN i[32]
    DIRECTION INPUT ;
    USE SIGNAL ;
    PORT
      LAYER M4 ;
        RECT  21.516 9.936 21.6 9.96 ;
    END
  END i[32]
  PIN i[33]
    DIRECTION INPUT ;
    USE SIGNAL ;
    PORT
      LAYER M4 ;
        RECT  21.516 10.032 21.6 10.056 ;
    END
  END i[33]
  PIN i[34]
    DIRECTION INPUT ;
    USE SIGNAL ;
    PORT
      LAYER M4 ;
        RECT  21.516 10.128 21.6 10.152 ;
    END
  END i[34]
  PIN i[35]
    DIRECTION INPUT ;
    USE SIGNAL ;
    PORT
      LAYER M4 ;
        RECT  21.516 10.224 21.6 10.248 ;
    END
  END i[35]
  PIN i[36]
    DIRECTION INPUT ;
    USE SIGNAL ;
    PORT
      LAYER M4 ;
        RECT  21.516 10.32 21.6 10.344 ;
    END
  END i[36]
  PIN i[37]
    DIRECTION INPUT ;
    USE SIGNAL ;
    PORT
      LAYER M4 ;
        RECT  21.516 10.416 21.6 10.44 ;
    END
  END i[37]
  PIN i[38]
    DIRECTION INPUT ;
    USE SIGNAL ;
    PORT
      LAYER M4 ;
        RECT  21.516 10.512 21.6 10.536 ;
    END
  END i[38]
  PIN i[39]
    DIRECTION INPUT ;
    USE SIGNAL ;
    PORT
      LAYER M4 ;
        RECT  21.516 10.608 21.6 10.632 ;
    END
  END i[39]
  PIN i[3]
    DIRECTION INPUT ;
    USE SIGNAL ;
    PORT
      LAYER M4 ;
        RECT  21.516 13.296 21.6 13.32 ;
    END
  END i[3]
  PIN i[40]
    DIRECTION INPUT ;
    USE SIGNAL ;
    PORT
      LAYER M4 ;
        RECT  21.516 10.704 21.6 10.728 ;
    END
  END i[40]
  PIN i[41]
    DIRECTION INPUT ;
    USE SIGNAL ;
    PORT
      LAYER M4 ;
        RECT  21.516 10.8 21.6 10.824 ;
    END
  END i[41]
  PIN i[42]
    DIRECTION INPUT ;
    USE SIGNAL ;
    PORT
      LAYER M4 ;
        RECT  21.516 10.896 21.6 10.92 ;
    END
  END i[42]
  PIN i[43]
    DIRECTION INPUT ;
    USE SIGNAL ;
    PORT
      LAYER M4 ;
        RECT  21.516 10.992 21.6 11.016 ;
    END
  END i[43]
  PIN i[44]
    DIRECTION INPUT ;
    USE SIGNAL ;
    PORT
      LAYER M4 ;
        RECT  21.516 11.088 21.6 11.112 ;
    END
  END i[44]
  PIN i[45]
    DIRECTION INPUT ;
    USE SIGNAL ;
    PORT
      LAYER M4 ;
        RECT  21.516 11.184 21.6 11.208 ;
    END
  END i[45]
  PIN i[46]
    DIRECTION INPUT ;
    USE SIGNAL ;
    PORT
      LAYER M4 ;
        RECT  21.516 11.28 21.6 11.304 ;
    END
  END i[46]
  PIN i[47]
    DIRECTION INPUT ;
    USE SIGNAL ;
    PORT
      LAYER M4 ;
        RECT  21.516 11.376 21.6 11.4 ;
    END
  END i[47]
  PIN i[48]
    DIRECTION INPUT ;
    USE SIGNAL ;
    PORT
      LAYER M4 ;
        RECT  21.516 11.472 21.6 11.496 ;
    END
  END i[48]
  PIN i[49]
    DIRECTION INPUT ;
    USE SIGNAL ;
    PORT
      LAYER M4 ;
        RECT  21.516 11.568 21.6 11.592 ;
    END
  END i[49]
  PIN i[4]
    DIRECTION INPUT ;
    USE SIGNAL ;
    PORT
      LAYER M4 ;
        RECT  21.516 13.392 21.6 13.416 ;
    END
  END i[4]
  PIN i[50]
    DIRECTION INPUT ;
    USE SIGNAL ;
    PORT
      LAYER M4 ;
        RECT  21.516 11.664 21.6 11.688 ;
    END
  END i[50]
  PIN i[51]
    DIRECTION INPUT ;
    USE SIGNAL ;
    PORT
      LAYER M4 ;
        RECT  21.516 11.76 21.6 11.784 ;
    END
  END i[51]
  PIN i[52]
    DIRECTION INPUT ;
    USE SIGNAL ;
    PORT
      LAYER M4 ;
        RECT  21.516 11.856 21.6 11.88 ;
    END
  END i[52]
  PIN i[53]
    DIRECTION INPUT ;
    USE SIGNAL ;
    PORT
      LAYER M4 ;
        RECT  21.516 11.952 21.6 11.976 ;
    END
  END i[53]
  PIN i[54]
    DIRECTION INPUT ;
    USE SIGNAL ;
    PORT
      LAYER M4 ;
        RECT  21.516 12.048 21.6 12.072 ;
    END
  END i[54]
  PIN i[55]
    DIRECTION INPUT ;
    USE SIGNAL ;
    PORT
      LAYER M4 ;
        RECT  21.516 12.144 21.6 12.168 ;
    END
  END i[55]
  PIN i[56]
    DIRECTION INPUT ;
    USE SIGNAL ;
    PORT
      LAYER M4 ;
        RECT  21.516 12.24 21.6 12.264 ;
    END
  END i[56]
  PIN i[57]
    DIRECTION INPUT ;
    USE SIGNAL ;
    PORT
      LAYER M4 ;
        RECT  21.516 12.336 21.6 12.36 ;
    END
  END i[57]
  PIN i[58]
    DIRECTION INPUT ;
    USE SIGNAL ;
    PORT
      LAYER M4 ;
        RECT  21.516 12.432 21.6 12.456 ;
    END
  END i[58]
  PIN i[59]
    DIRECTION INPUT ;
    USE SIGNAL ;
    PORT
      LAYER M4 ;
        RECT  21.516 12.528 21.6 12.552 ;
    END
  END i[59]
  PIN i[5]
    DIRECTION INPUT ;
    USE SIGNAL ;
    PORT
      LAYER M4 ;
        RECT  21.516 13.488 21.6 13.512 ;
    END
  END i[5]
  PIN i[60]
    DIRECTION INPUT ;
    USE SIGNAL ;
    PORT
      LAYER M4 ;
        RECT  21.516 12.624 21.6 12.648 ;
    END
  END i[60]
  PIN i[61]
    DIRECTION INPUT ;
    USE SIGNAL ;
    PORT
      LAYER M4 ;
        RECT  21.516 12.72 21.6 12.744 ;
    END
  END i[61]
  PIN i[62]
    DIRECTION INPUT ;
    USE SIGNAL ;
    PORT
      LAYER M4 ;
        RECT  21.516 12.816 21.6 12.84 ;
    END
  END i[62]
  PIN i[63]
    DIRECTION INPUT ;
    USE SIGNAL ;
    PORT
      LAYER M4 ;
        RECT  21.516 12.912 21.6 12.936 ;
    END
  END i[63]
  PIN i[64]
    DIRECTION INPUT ;
    USE SIGNAL ;
    PORT
      LAYER M4 ;
        RECT  21.516 0.72 21.6 0.744 ;
    END
  END i[64]
  PIN i[65]
    DIRECTION INPUT ;
    USE SIGNAL ;
    PORT
      LAYER M4 ;
        RECT  21.516 0.816 21.6 0.84 ;
    END
  END i[65]
  PIN i[66]
    DIRECTION INPUT ;
    USE SIGNAL ;
    PORT
      LAYER M4 ;
        RECT  21.516 0.912 21.6 0.936 ;
    END
  END i[66]
  PIN i[67]
    DIRECTION INPUT ;
    USE SIGNAL ;
    PORT
      LAYER M4 ;
        RECT  21.516 1.008 21.6 1.032 ;
    END
  END i[67]
  PIN i[68]
    DIRECTION INPUT ;
    USE SIGNAL ;
    PORT
      LAYER M4 ;
        RECT  21.516 1.104 21.6 1.128 ;
    END
  END i[68]
  PIN i[69]
    DIRECTION INPUT ;
    USE SIGNAL ;
    PORT
      LAYER M4 ;
        RECT  21.516 1.2 21.6 1.224 ;
    END
  END i[69]
  PIN i[6]
    DIRECTION INPUT ;
    USE SIGNAL ;
    PORT
      LAYER M4 ;
        RECT  21.516 13.584 21.6 13.608 ;
    END
  END i[6]
  PIN i[70]
    DIRECTION INPUT ;
    USE SIGNAL ;
    PORT
      LAYER M4 ;
        RECT  21.516 1.296 21.6 1.32 ;
    END
  END i[70]
  PIN i[71]
    DIRECTION INPUT ;
    USE SIGNAL ;
    PORT
      LAYER M4 ;
        RECT  21.516 1.392 21.6 1.416 ;
    END
  END i[71]
  PIN i[72]
    DIRECTION INPUT ;
    USE SIGNAL ;
    PORT
      LAYER M4 ;
        RECT  21.516 1.488 21.6 1.512 ;
    END
  END i[72]
  PIN i[73]
    DIRECTION INPUT ;
    USE SIGNAL ;
    PORT
      LAYER M4 ;
        RECT  21.516 1.584 21.6 1.608 ;
    END
  END i[73]
  PIN i[74]
    DIRECTION INPUT ;
    USE SIGNAL ;
    PORT
      LAYER M4 ;
        RECT  21.516 1.68 21.6 1.704 ;
    END
  END i[74]
  PIN i[75]
    DIRECTION INPUT ;
    USE SIGNAL ;
    PORT
      LAYER M4 ;
        RECT  21.516 1.776 21.6 1.8 ;
    END
  END i[75]
  PIN i[76]
    DIRECTION INPUT ;
    USE SIGNAL ;
    PORT
      LAYER M4 ;
        RECT  21.516 1.872 21.6 1.896 ;
    END
  END i[76]
  PIN i[77]
    DIRECTION INPUT ;
    USE SIGNAL ;
    PORT
      LAYER M4 ;
        RECT  21.516 1.968 21.6 1.992 ;
    END
  END i[77]
  PIN i[78]
    DIRECTION INPUT ;
    USE SIGNAL ;
    PORT
      LAYER M4 ;
        RECT  21.516 2.064 21.6 2.088 ;
    END
  END i[78]
  PIN i[79]
    DIRECTION INPUT ;
    USE SIGNAL ;
    PORT
      LAYER M4 ;
        RECT  21.516 2.16 21.6 2.184 ;
    END
  END i[79]
  PIN i[7]
    DIRECTION INPUT ;
    USE SIGNAL ;
    PORT
      LAYER M4 ;
        RECT  21.516 13.68 21.6 13.704 ;
    END
  END i[7]
  PIN i[80]
    DIRECTION INPUT ;
    USE SIGNAL ;
    PORT
      LAYER M4 ;
        RECT  21.516 2.256 21.6 2.28 ;
    END
  END i[80]
  PIN i[81]
    DIRECTION INPUT ;
    USE SIGNAL ;
    PORT
      LAYER M4 ;
        RECT  21.516 2.352 21.6 2.376 ;
    END
  END i[81]
  PIN i[82]
    DIRECTION INPUT ;
    USE SIGNAL ;
    PORT
      LAYER M4 ;
        RECT  21.516 2.448 21.6 2.472 ;
    END
  END i[82]
  PIN i[83]
    DIRECTION INPUT ;
    USE SIGNAL ;
    PORT
      LAYER M4 ;
        RECT  21.516 2.544 21.6 2.568 ;
    END
  END i[83]
  PIN i[84]
    DIRECTION INPUT ;
    USE SIGNAL ;
    PORT
      LAYER M4 ;
        RECT  21.516 2.64 21.6 2.664 ;
    END
  END i[84]
  PIN i[85]
    DIRECTION INPUT ;
    USE SIGNAL ;
    PORT
      LAYER M4 ;
        RECT  21.516 2.736 21.6 2.76 ;
    END
  END i[85]
  PIN i[86]
    DIRECTION INPUT ;
    USE SIGNAL ;
    PORT
      LAYER M4 ;
        RECT  21.516 2.832 21.6 2.856 ;
    END
  END i[86]
  PIN i[87]
    DIRECTION INPUT ;
    USE SIGNAL ;
    PORT
      LAYER M4 ;
        RECT  21.516 2.928 21.6 2.952 ;
    END
  END i[87]
  PIN i[88]
    DIRECTION INPUT ;
    USE SIGNAL ;
    PORT
      LAYER M4 ;
        RECT  21.516 3.024 21.6 3.048 ;
    END
  END i[88]
  PIN i[89]
    DIRECTION INPUT ;
    USE SIGNAL ;
    PORT
      LAYER M4 ;
        RECT  21.516 3.12 21.6 3.144 ;
    END
  END i[89]
  PIN i[8]
    DIRECTION INPUT ;
    USE SIGNAL ;
    PORT
      LAYER M4 ;
        RECT  21.516 13.776 21.6 13.8 ;
    END
  END i[8]
  PIN i[90]
    DIRECTION INPUT ;
    USE SIGNAL ;
    PORT
      LAYER M4 ;
        RECT  21.516 3.216 21.6 3.24 ;
    END
  END i[90]
  PIN i[91]
    DIRECTION INPUT ;
    USE SIGNAL ;
    PORT
      LAYER M4 ;
        RECT  21.516 3.312 21.6 3.336 ;
    END
  END i[91]
  PIN i[92]
    DIRECTION INPUT ;
    USE SIGNAL ;
    PORT
      LAYER M4 ;
        RECT  21.516 3.408 21.6 3.432 ;
    END
  END i[92]
  PIN i[93]
    DIRECTION INPUT ;
    USE SIGNAL ;
    PORT
      LAYER M4 ;
        RECT  21.516 3.504 21.6 3.528 ;
    END
  END i[93]
  PIN i[94]
    DIRECTION INPUT ;
    USE SIGNAL ;
    PORT
      LAYER M4 ;
        RECT  21.516 3.6 21.6 3.624 ;
    END
  END i[94]
  PIN i[95]
    DIRECTION INPUT ;
    USE SIGNAL ;
    PORT
      LAYER M4 ;
        RECT  21.516 3.696 21.6 3.72 ;
    END
  END i[95]
  PIN i[96]
    DIRECTION INPUT ;
    USE SIGNAL ;
    PORT
      LAYER M4 ;
        RECT  21.516 6.864 21.6 6.888 ;
    END
  END i[96]
  PIN i[97]
    DIRECTION INPUT ;
    USE SIGNAL ;
    PORT
      LAYER M4 ;
        RECT  21.516 6.96 21.6 6.984 ;
    END
  END i[97]
  PIN i[98]
    DIRECTION INPUT ;
    USE SIGNAL ;
    PORT
      LAYER M4 ;
        RECT  21.516 7.056 21.6 7.08 ;
    END
  END i[98]
  PIN i[99]
    DIRECTION INPUT ;
    USE SIGNAL ;
    PORT
      LAYER M4 ;
        RECT  21.516 7.152 21.6 7.176 ;
    END
  END i[99]
  PIN i[9]
    DIRECTION INPUT ;
    USE SIGNAL ;
    PORT
      LAYER M4 ;
        RECT  21.516 13.872 21.6 13.896 ;
    END
  END i[9]
  PIN o[0]
    DIRECTION OUTPUT ;
    USE SIGNAL ;
    PORT
      LAYER M4 ;
        RECT  0 18.48 0.084 18.504 ;
    END
  END o[0]
  PIN o[100]
    DIRECTION OUTPUT ;
    USE SIGNAL ;
    PORT
      LAYER M4 ;
        RECT  0 21.936 0.084 21.96 ;
    END
  END o[100]
  PIN o[101]
    DIRECTION OUTPUT ;
    USE SIGNAL ;
    PORT
      LAYER M4 ;
        RECT  0 22.032 0.084 22.056 ;
    END
  END o[101]
  PIN o[102]
    DIRECTION OUTPUT ;
    USE SIGNAL ;
    PORT
      LAYER M4 ;
        RECT  0 22.128 0.084 22.152 ;
    END
  END o[102]
  PIN o[103]
    DIRECTION OUTPUT ;
    USE SIGNAL ;
    PORT
      LAYER M4 ;
        RECT  0 22.224 0.084 22.248 ;
    END
  END o[103]
  PIN o[104]
    DIRECTION OUTPUT ;
    USE SIGNAL ;
    PORT
      LAYER M4 ;
        RECT  0 22.32 0.084 22.344 ;
    END
  END o[104]
  PIN o[105]
    DIRECTION OUTPUT ;
    USE SIGNAL ;
    PORT
      LAYER M4 ;
        RECT  0 22.416 0.084 22.44 ;
    END
  END o[105]
  PIN o[106]
    DIRECTION OUTPUT ;
    USE SIGNAL ;
    PORT
      LAYER M4 ;
        RECT  0 22.512 0.084 22.536 ;
    END
  END o[106]
  PIN o[107]
    DIRECTION OUTPUT ;
    USE SIGNAL ;
    PORT
      LAYER M4 ;
        RECT  0 22.608 0.084 22.632 ;
    END
  END o[107]
  PIN o[108]
    DIRECTION OUTPUT ;
    USE SIGNAL ;
    PORT
      LAYER M4 ;
        RECT  0 22.704 0.084 22.728 ;
    END
  END o[108]
  PIN o[109]
    DIRECTION OUTPUT ;
    USE SIGNAL ;
    PORT
      LAYER M4 ;
        RECT  0 22.8 0.084 22.824 ;
    END
  END o[109]
  PIN o[10]
    DIRECTION OUTPUT ;
    USE SIGNAL ;
    PORT
      LAYER M4 ;
        RECT  0 19.44 0.084 19.464 ;
    END
  END o[10]
  PIN o[110]
    DIRECTION OUTPUT ;
    USE SIGNAL ;
    PORT
      LAYER M4 ;
        RECT  0 22.896 0.084 22.92 ;
    END
  END o[110]
  PIN o[111]
    DIRECTION OUTPUT ;
    USE SIGNAL ;
    PORT
      LAYER M4 ;
        RECT  0 22.992 0.084 23.016 ;
    END
  END o[111]
  PIN o[112]
    DIRECTION OUTPUT ;
    USE SIGNAL ;
    PORT
      LAYER M4 ;
        RECT  0 23.088 0.084 23.112 ;
    END
  END o[112]
  PIN o[113]
    DIRECTION OUTPUT ;
    USE SIGNAL ;
    PORT
      LAYER M4 ;
        RECT  0 23.184 0.084 23.208 ;
    END
  END o[113]
  PIN o[114]
    DIRECTION OUTPUT ;
    USE SIGNAL ;
    PORT
      LAYER M4 ;
        RECT  0 23.28 0.084 23.304 ;
    END
  END o[114]
  PIN o[115]
    DIRECTION OUTPUT ;
    USE SIGNAL ;
    PORT
      LAYER M4 ;
        RECT  0 23.376 0.084 23.4 ;
    END
  END o[115]
  PIN o[116]
    DIRECTION OUTPUT ;
    USE SIGNAL ;
    PORT
      LAYER M4 ;
        RECT  0 23.472 0.084 23.496 ;
    END
  END o[116]
  PIN o[117]
    DIRECTION OUTPUT ;
    USE SIGNAL ;
    PORT
      LAYER M4 ;
        RECT  0 23.568 0.084 23.592 ;
    END
  END o[117]
  PIN o[118]
    DIRECTION OUTPUT ;
    USE SIGNAL ;
    PORT
      LAYER M4 ;
        RECT  0 23.664 0.084 23.688 ;
    END
  END o[118]
  PIN o[119]
    DIRECTION OUTPUT ;
    USE SIGNAL ;
    PORT
      LAYER M4 ;
        RECT  0 23.76 0.084 23.784 ;
    END
  END o[119]
  PIN o[11]
    DIRECTION OUTPUT ;
    USE SIGNAL ;
    PORT
      LAYER M4 ;
        RECT  0 19.536 0.084 19.56 ;
    END
  END o[11]
  PIN o[120]
    DIRECTION OUTPUT ;
    USE SIGNAL ;
    PORT
      LAYER M4 ;
        RECT  0 23.856 0.084 23.88 ;
    END
  END o[120]
  PIN o[121]
    DIRECTION OUTPUT ;
    USE SIGNAL ;
    PORT
      LAYER M4 ;
        RECT  0 23.952 0.084 23.976 ;
    END
  END o[121]
  PIN o[122]
    DIRECTION OUTPUT ;
    USE SIGNAL ;
    PORT
      LAYER M4 ;
        RECT  0 24.048 0.084 24.072 ;
    END
  END o[122]
  PIN o[123]
    DIRECTION OUTPUT ;
    USE SIGNAL ;
    PORT
      LAYER M4 ;
        RECT  0 24.144 0.084 24.168 ;
    END
  END o[123]
  PIN o[124]
    DIRECTION OUTPUT ;
    USE SIGNAL ;
    PORT
      LAYER M4 ;
        RECT  0 24.24 0.084 24.264 ;
    END
  END o[124]
  PIN o[125]
    DIRECTION OUTPUT ;
    USE SIGNAL ;
    PORT
      LAYER M4 ;
        RECT  0 24.336 0.084 24.36 ;
    END
  END o[125]
  PIN o[126]
    DIRECTION OUTPUT ;
    USE SIGNAL ;
    PORT
      LAYER M4 ;
        RECT  0 24.432 0.084 24.456 ;
    END
  END o[126]
  PIN o[127]
    DIRECTION OUTPUT ;
    USE SIGNAL ;
    PORT
      LAYER M4 ;
        RECT  0 24.528 0.084 24.552 ;
    END
  END o[127]
  PIN o[128]
    DIRECTION OUTPUT ;
    USE SIGNAL ;
    PORT
      LAYER M4 ;
        RECT  0 24.624 0.084 24.648 ;
    END
  END o[128]
  PIN o[129]
    DIRECTION OUTPUT ;
    USE SIGNAL ;
    PORT
      LAYER M4 ;
        RECT  0 24.72 0.084 24.744 ;
    END
  END o[129]
  PIN o[12]
    DIRECTION OUTPUT ;
    USE SIGNAL ;
    PORT
      LAYER M4 ;
        RECT  0 19.632 0.084 19.656 ;
    END
  END o[12]
  PIN o[130]
    DIRECTION OUTPUT ;
    USE SIGNAL ;
    PORT
      LAYER M4 ;
        RECT  0 24.816 0.084 24.84 ;
    END
  END o[130]
  PIN o[131]
    DIRECTION OUTPUT ;
    USE SIGNAL ;
    PORT
      LAYER M4 ;
        RECT  0 24.912 0.084 24.936 ;
    END
  END o[131]
  PIN o[132]
    DIRECTION OUTPUT ;
    USE SIGNAL ;
    PORT
      LAYER M4 ;
        RECT  0 25.008 0.084 25.032 ;
    END
  END o[132]
  PIN o[133]
    DIRECTION OUTPUT ;
    USE SIGNAL ;
    PORT
      LAYER M4 ;
        RECT  0 25.104 0.084 25.128 ;
    END
  END o[133]
  PIN o[134]
    DIRECTION OUTPUT ;
    USE SIGNAL ;
    PORT
      LAYER M4 ;
        RECT  0 25.2 0.084 25.224 ;
    END
  END o[134]
  PIN o[135]
    DIRECTION OUTPUT ;
    USE SIGNAL ;
    PORT
      LAYER M4 ;
        RECT  0 25.296 0.084 25.32 ;
    END
  END o[135]
  PIN o[136]
    DIRECTION OUTPUT ;
    USE SIGNAL ;
    PORT
      LAYER M4 ;
        RECT  0 25.392 0.084 25.416 ;
    END
  END o[136]
  PIN o[137]
    DIRECTION OUTPUT ;
    USE SIGNAL ;
    PORT
      LAYER M4 ;
        RECT  0 25.488 0.084 25.512 ;
    END
  END o[137]
  PIN o[138]
    DIRECTION OUTPUT ;
    USE SIGNAL ;
    PORT
      LAYER M4 ;
        RECT  0 25.584 0.084 25.608 ;
    END
  END o[138]
  PIN o[139]
    DIRECTION OUTPUT ;
    USE SIGNAL ;
    PORT
      LAYER M4 ;
        RECT  0 25.68 0.084 25.704 ;
    END
  END o[139]
  PIN o[13]
    DIRECTION OUTPUT ;
    USE SIGNAL ;
    PORT
      LAYER M4 ;
        RECT  0 19.728 0.084 19.752 ;
    END
  END o[13]
  PIN o[140]
    DIRECTION OUTPUT ;
    USE SIGNAL ;
    PORT
      LAYER M4 ;
        RECT  0 25.776 0.084 25.8 ;
    END
  END o[140]
  PIN o[141]
    DIRECTION OUTPUT ;
    USE SIGNAL ;
    PORT
      LAYER M4 ;
        RECT  0 25.872 0.084 25.896 ;
    END
  END o[141]
  PIN o[142]
    DIRECTION OUTPUT ;
    USE SIGNAL ;
    PORT
      LAYER M4 ;
        RECT  0 25.968 0.084 25.992 ;
    END
  END o[142]
  PIN o[143]
    DIRECTION OUTPUT ;
    USE SIGNAL ;
    PORT
      LAYER M4 ;
        RECT  0 26.064 0.084 26.088 ;
    END
  END o[143]
  PIN o[144]
    DIRECTION OUTPUT ;
    USE SIGNAL ;
    PORT
      LAYER M4 ;
        RECT  0 26.16 0.084 26.184 ;
    END
  END o[144]
  PIN o[145]
    DIRECTION OUTPUT ;
    USE SIGNAL ;
    PORT
      LAYER M4 ;
        RECT  0 26.256 0.084 26.28 ;
    END
  END o[145]
  PIN o[146]
    DIRECTION OUTPUT ;
    USE SIGNAL ;
    PORT
      LAYER M4 ;
        RECT  0 26.352 0.084 26.376 ;
    END
  END o[146]
  PIN o[147]
    DIRECTION OUTPUT ;
    USE SIGNAL ;
    PORT
      LAYER M4 ;
        RECT  0 26.448 0.084 26.472 ;
    END
  END o[147]
  PIN o[148]
    DIRECTION OUTPUT ;
    USE SIGNAL ;
    PORT
      LAYER M4 ;
        RECT  0 26.544 0.084 26.568 ;
    END
  END o[148]
  PIN o[149]
    DIRECTION OUTPUT ;
    USE SIGNAL ;
    PORT
      LAYER M4 ;
        RECT  0 26.64 0.084 26.664 ;
    END
  END o[149]
  PIN o[14]
    DIRECTION OUTPUT ;
    USE SIGNAL ;
    PORT
      LAYER M4 ;
        RECT  0 19.824 0.084 19.848 ;
    END
  END o[14]
  PIN o[150]
    DIRECTION OUTPUT ;
    USE SIGNAL ;
    PORT
      LAYER M4 ;
        RECT  0 26.736 0.084 26.76 ;
    END
  END o[150]
  PIN o[151]
    DIRECTION OUTPUT ;
    USE SIGNAL ;
    PORT
      LAYER M4 ;
        RECT  0 26.832 0.084 26.856 ;
    END
  END o[151]
  PIN o[152]
    DIRECTION OUTPUT ;
    USE SIGNAL ;
    PORT
      LAYER M4 ;
        RECT  0 26.928 0.084 26.952 ;
    END
  END o[152]
  PIN o[153]
    DIRECTION OUTPUT ;
    USE SIGNAL ;
    PORT
      LAYER M4 ;
        RECT  0 27.024 0.084 27.048 ;
    END
  END o[153]
  PIN o[154]
    DIRECTION OUTPUT ;
    USE SIGNAL ;
    PORT
      LAYER M4 ;
        RECT  0 27.12 0.084 27.144 ;
    END
  END o[154]
  PIN o[155]
    DIRECTION OUTPUT ;
    USE SIGNAL ;
    PORT
      LAYER M4 ;
        RECT  0 27.216 0.084 27.24 ;
    END
  END o[155]
  PIN o[156]
    DIRECTION OUTPUT ;
    USE SIGNAL ;
    PORT
      LAYER M4 ;
        RECT  0 27.312 0.084 27.336 ;
    END
  END o[156]
  PIN o[157]
    DIRECTION OUTPUT ;
    USE SIGNAL ;
    PORT
      LAYER M4 ;
        RECT  0 27.408 0.084 27.432 ;
    END
  END o[157]
  PIN o[158]
    DIRECTION OUTPUT ;
    USE SIGNAL ;
    PORT
      LAYER M4 ;
        RECT  0 27.504 0.084 27.528 ;
    END
  END o[158]
  PIN o[159]
    DIRECTION OUTPUT ;
    USE SIGNAL ;
    PORT
      LAYER M4 ;
        RECT  0 27.6 0.084 27.624 ;
    END
  END o[159]
  PIN o[15]
    DIRECTION OUTPUT ;
    USE SIGNAL ;
    PORT
      LAYER M4 ;
        RECT  0 19.92 0.084 19.944 ;
    END
  END o[15]
  PIN o[160]
    DIRECTION OUTPUT ;
    USE SIGNAL ;
    PORT
      LAYER M4 ;
        RECT  0 5.424 0.084 5.448 ;
    END
  END o[160]
  PIN o[161]
    DIRECTION OUTPUT ;
    USE SIGNAL ;
    PORT
      LAYER M4 ;
        RECT  0 5.52 0.084 5.544 ;
    END
  END o[161]
  PIN o[162]
    DIRECTION OUTPUT ;
    USE SIGNAL ;
    PORT
      LAYER M4 ;
        RECT  0 5.616 0.084 5.64 ;
    END
  END o[162]
  PIN o[163]
    DIRECTION OUTPUT ;
    USE SIGNAL ;
    PORT
      LAYER M4 ;
        RECT  0 5.712 0.084 5.736 ;
    END
  END o[163]
  PIN o[164]
    DIRECTION OUTPUT ;
    USE SIGNAL ;
    PORT
      LAYER M4 ;
        RECT  0 5.808 0.084 5.832 ;
    END
  END o[164]
  PIN o[165]
    DIRECTION OUTPUT ;
    USE SIGNAL ;
    PORT
      LAYER M4 ;
        RECT  0 5.904 0.084 5.928 ;
    END
  END o[165]
  PIN o[166]
    DIRECTION OUTPUT ;
    USE SIGNAL ;
    PORT
      LAYER M4 ;
        RECT  0 6 0.084 6.024 ;
    END
  END o[166]
  PIN o[167]
    DIRECTION OUTPUT ;
    USE SIGNAL ;
    PORT
      LAYER M4 ;
        RECT  0 6.096 0.084 6.12 ;
    END
  END o[167]
  PIN o[168]
    DIRECTION OUTPUT ;
    USE SIGNAL ;
    PORT
      LAYER M4 ;
        RECT  0 6.192 0.084 6.216 ;
    END
  END o[168]
  PIN o[169]
    DIRECTION OUTPUT ;
    USE SIGNAL ;
    PORT
      LAYER M4 ;
        RECT  0 6.288 0.084 6.312 ;
    END
  END o[169]
  PIN o[16]
    DIRECTION OUTPUT ;
    USE SIGNAL ;
    PORT
      LAYER M4 ;
        RECT  0 20.016 0.084 20.04 ;
    END
  END o[16]
  PIN o[170]
    DIRECTION OUTPUT ;
    USE SIGNAL ;
    PORT
      LAYER M4 ;
        RECT  0 6.384 0.084 6.408 ;
    END
  END o[170]
  PIN o[171]
    DIRECTION OUTPUT ;
    USE SIGNAL ;
    PORT
      LAYER M4 ;
        RECT  0 6.48 0.084 6.504 ;
    END
  END o[171]
  PIN o[172]
    DIRECTION OUTPUT ;
    USE SIGNAL ;
    PORT
      LAYER M4 ;
        RECT  0 6.576 0.084 6.6 ;
    END
  END o[172]
  PIN o[173]
    DIRECTION OUTPUT ;
    USE SIGNAL ;
    PORT
      LAYER M4 ;
        RECT  0 6.672 0.084 6.696 ;
    END
  END o[173]
  PIN o[174]
    DIRECTION OUTPUT ;
    USE SIGNAL ;
    PORT
      LAYER M4 ;
        RECT  0 6.768 0.084 6.792 ;
    END
  END o[174]
  PIN o[175]
    DIRECTION OUTPUT ;
    USE SIGNAL ;
    PORT
      LAYER M4 ;
        RECT  0 6.864 0.084 6.888 ;
    END
  END o[175]
  PIN o[176]
    DIRECTION OUTPUT ;
    USE SIGNAL ;
    PORT
      LAYER M4 ;
        RECT  0 6.96 0.084 6.984 ;
    END
  END o[176]
  PIN o[177]
    DIRECTION OUTPUT ;
    USE SIGNAL ;
    PORT
      LAYER M4 ;
        RECT  0 7.056 0.084 7.08 ;
    END
  END o[177]
  PIN o[178]
    DIRECTION OUTPUT ;
    USE SIGNAL ;
    PORT
      LAYER M4 ;
        RECT  0 7.152 0.084 7.176 ;
    END
  END o[178]
  PIN o[179]
    DIRECTION OUTPUT ;
    USE SIGNAL ;
    PORT
      LAYER M4 ;
        RECT  0 7.248 0.084 7.272 ;
    END
  END o[179]
  PIN o[17]
    DIRECTION OUTPUT ;
    USE SIGNAL ;
    PORT
      LAYER M4 ;
        RECT  0 20.112 0.084 20.136 ;
    END
  END o[17]
  PIN o[180]
    DIRECTION OUTPUT ;
    USE SIGNAL ;
    PORT
      LAYER M4 ;
        RECT  0 7.344 0.084 7.368 ;
    END
  END o[180]
  PIN o[181]
    DIRECTION OUTPUT ;
    USE SIGNAL ;
    PORT
      LAYER M4 ;
        RECT  0 7.44 0.084 7.464 ;
    END
  END o[181]
  PIN o[182]
    DIRECTION OUTPUT ;
    USE SIGNAL ;
    PORT
      LAYER M4 ;
        RECT  0 7.536 0.084 7.56 ;
    END
  END o[182]
  PIN o[183]
    DIRECTION OUTPUT ;
    USE SIGNAL ;
    PORT
      LAYER M4 ;
        RECT  0 7.632 0.084 7.656 ;
    END
  END o[183]
  PIN o[184]
    DIRECTION OUTPUT ;
    USE SIGNAL ;
    PORT
      LAYER M4 ;
        RECT  0 7.728 0.084 7.752 ;
    END
  END o[184]
  PIN o[185]
    DIRECTION OUTPUT ;
    USE SIGNAL ;
    PORT
      LAYER M4 ;
        RECT  0 7.824 0.084 7.848 ;
    END
  END o[185]
  PIN o[186]
    DIRECTION OUTPUT ;
    USE SIGNAL ;
    PORT
      LAYER M4 ;
        RECT  0 7.92 0.084 7.944 ;
    END
  END o[186]
  PIN o[187]
    DIRECTION OUTPUT ;
    USE SIGNAL ;
    PORT
      LAYER M4 ;
        RECT  0 8.016 0.084 8.04 ;
    END
  END o[187]
  PIN o[188]
    DIRECTION OUTPUT ;
    USE SIGNAL ;
    PORT
      LAYER M4 ;
        RECT  0 8.112 0.084 8.136 ;
    END
  END o[188]
  PIN o[189]
    DIRECTION OUTPUT ;
    USE SIGNAL ;
    PORT
      LAYER M4 ;
        RECT  0 8.208 0.084 8.232 ;
    END
  END o[189]
  PIN o[18]
    DIRECTION OUTPUT ;
    USE SIGNAL ;
    PORT
      LAYER M4 ;
        RECT  0 20.208 0.084 20.232 ;
    END
  END o[18]
  PIN o[190]
    DIRECTION OUTPUT ;
    USE SIGNAL ;
    PORT
      LAYER M4 ;
        RECT  0 8.304 0.084 8.328 ;
    END
  END o[190]
  PIN o[191]
    DIRECTION OUTPUT ;
    USE SIGNAL ;
    PORT
      LAYER M4 ;
        RECT  0 8.4 0.084 8.424 ;
    END
  END o[191]
  PIN o[192]
    DIRECTION OUTPUT ;
    USE SIGNAL ;
    PORT
      LAYER M4 ;
        RECT  0 15.408 0.084 15.432 ;
    END
  END o[192]
  PIN o[193]
    DIRECTION OUTPUT ;
    USE SIGNAL ;
    PORT
      LAYER M4 ;
        RECT  0 15.504 0.084 15.528 ;
    END
  END o[193]
  PIN o[194]
    DIRECTION OUTPUT ;
    USE SIGNAL ;
    PORT
      LAYER M4 ;
        RECT  0 15.6 0.084 15.624 ;
    END
  END o[194]
  PIN o[195]
    DIRECTION OUTPUT ;
    USE SIGNAL ;
    PORT
      LAYER M4 ;
        RECT  0 15.696 0.084 15.72 ;
    END
  END o[195]
  PIN o[196]
    DIRECTION OUTPUT ;
    USE SIGNAL ;
    PORT
      LAYER M4 ;
        RECT  0 15.792 0.084 15.816 ;
    END
  END o[196]
  PIN o[197]
    DIRECTION OUTPUT ;
    USE SIGNAL ;
    PORT
      LAYER M4 ;
        RECT  0 15.888 0.084 15.912 ;
    END
  END o[197]
  PIN o[198]
    DIRECTION OUTPUT ;
    USE SIGNAL ;
    PORT
      LAYER M4 ;
        RECT  0 15.984 0.084 16.008 ;
    END
  END o[198]
  PIN o[199]
    DIRECTION OUTPUT ;
    USE SIGNAL ;
    PORT
      LAYER M4 ;
        RECT  0 16.08 0.084 16.104 ;
    END
  END o[199]
  PIN o[19]
    DIRECTION OUTPUT ;
    USE SIGNAL ;
    PORT
      LAYER M4 ;
        RECT  0 20.304 0.084 20.328 ;
    END
  END o[19]
  PIN o[1]
    DIRECTION OUTPUT ;
    USE SIGNAL ;
    PORT
      LAYER M4 ;
        RECT  0 18.576 0.084 18.6 ;
    END
  END o[1]
  PIN o[200]
    DIRECTION OUTPUT ;
    USE SIGNAL ;
    PORT
      LAYER M4 ;
        RECT  0 16.176 0.084 16.2 ;
    END
  END o[200]
  PIN o[201]
    DIRECTION OUTPUT ;
    USE SIGNAL ;
    PORT
      LAYER M4 ;
        RECT  0 16.272 0.084 16.296 ;
    END
  END o[201]
  PIN o[202]
    DIRECTION OUTPUT ;
    USE SIGNAL ;
    PORT
      LAYER M4 ;
        RECT  0 16.368 0.084 16.392 ;
    END
  END o[202]
  PIN o[203]
    DIRECTION OUTPUT ;
    USE SIGNAL ;
    PORT
      LAYER M4 ;
        RECT  0 16.464 0.084 16.488 ;
    END
  END o[203]
  PIN o[204]
    DIRECTION OUTPUT ;
    USE SIGNAL ;
    PORT
      LAYER M4 ;
        RECT  0 16.56 0.084 16.584 ;
    END
  END o[204]
  PIN o[205]
    DIRECTION OUTPUT ;
    USE SIGNAL ;
    PORT
      LAYER M4 ;
        RECT  0 16.656 0.084 16.68 ;
    END
  END o[205]
  PIN o[206]
    DIRECTION OUTPUT ;
    USE SIGNAL ;
    PORT
      LAYER M4 ;
        RECT  0 16.752 0.084 16.776 ;
    END
  END o[206]
  PIN o[207]
    DIRECTION OUTPUT ;
    USE SIGNAL ;
    PORT
      LAYER M4 ;
        RECT  0 16.848 0.084 16.872 ;
    END
  END o[207]
  PIN o[208]
    DIRECTION OUTPUT ;
    USE SIGNAL ;
    PORT
      LAYER M4 ;
        RECT  0 16.944 0.084 16.968 ;
    END
  END o[208]
  PIN o[209]
    DIRECTION OUTPUT ;
    USE SIGNAL ;
    PORT
      LAYER M4 ;
        RECT  0 17.04 0.084 17.064 ;
    END
  END o[209]
  PIN o[20]
    DIRECTION OUTPUT ;
    USE SIGNAL ;
    PORT
      LAYER M4 ;
        RECT  0 20.4 0.084 20.424 ;
    END
  END o[20]
  PIN o[210]
    DIRECTION OUTPUT ;
    USE SIGNAL ;
    PORT
      LAYER M4 ;
        RECT  0 17.136 0.084 17.16 ;
    END
  END o[210]
  PIN o[211]
    DIRECTION OUTPUT ;
    USE SIGNAL ;
    PORT
      LAYER M4 ;
        RECT  0 17.232 0.084 17.256 ;
    END
  END o[211]
  PIN o[212]
    DIRECTION OUTPUT ;
    USE SIGNAL ;
    PORT
      LAYER M4 ;
        RECT  0 17.328 0.084 17.352 ;
    END
  END o[212]
  PIN o[213]
    DIRECTION OUTPUT ;
    USE SIGNAL ;
    PORT
      LAYER M4 ;
        RECT  0 17.424 0.084 17.448 ;
    END
  END o[213]
  PIN o[214]
    DIRECTION OUTPUT ;
    USE SIGNAL ;
    PORT
      LAYER M4 ;
        RECT  0 17.52 0.084 17.544 ;
    END
  END o[214]
  PIN o[215]
    DIRECTION OUTPUT ;
    USE SIGNAL ;
    PORT
      LAYER M4 ;
        RECT  0 17.616 0.084 17.64 ;
    END
  END o[215]
  PIN o[216]
    DIRECTION OUTPUT ;
    USE SIGNAL ;
    PORT
      LAYER M4 ;
        RECT  0 17.712 0.084 17.736 ;
    END
  END o[216]
  PIN o[217]
    DIRECTION OUTPUT ;
    USE SIGNAL ;
    PORT
      LAYER M4 ;
        RECT  0 17.808 0.084 17.832 ;
    END
  END o[217]
  PIN o[218]
    DIRECTION OUTPUT ;
    USE SIGNAL ;
    PORT
      LAYER M4 ;
        RECT  0 17.904 0.084 17.928 ;
    END
  END o[218]
  PIN o[219]
    DIRECTION OUTPUT ;
    USE SIGNAL ;
    PORT
      LAYER M4 ;
        RECT  0 18 0.084 18.024 ;
    END
  END o[219]
  PIN o[21]
    DIRECTION OUTPUT ;
    USE SIGNAL ;
    PORT
      LAYER M4 ;
        RECT  0 20.496 0.084 20.52 ;
    END
  END o[21]
  PIN o[220]
    DIRECTION OUTPUT ;
    USE SIGNAL ;
    PORT
      LAYER M4 ;
        RECT  0 18.096 0.084 18.12 ;
    END
  END o[220]
  PIN o[221]
    DIRECTION OUTPUT ;
    USE SIGNAL ;
    PORT
      LAYER M4 ;
        RECT  0 18.192 0.084 18.216 ;
    END
  END o[221]
  PIN o[222]
    DIRECTION OUTPUT ;
    USE SIGNAL ;
    PORT
      LAYER M4 ;
        RECT  0 18.288 0.084 18.312 ;
    END
  END o[222]
  PIN o[223]
    DIRECTION OUTPUT ;
    USE SIGNAL ;
    PORT
      LAYER M4 ;
        RECT  0 18.384 0.084 18.408 ;
    END
  END o[223]
  PIN o[224]
    DIRECTION OUTPUT ;
    USE SIGNAL ;
    PORT
      LAYER M4 ;
        RECT  0 8.496 0.084 8.52 ;
    END
  END o[224]
  PIN o[225]
    DIRECTION OUTPUT ;
    USE SIGNAL ;
    PORT
      LAYER M4 ;
        RECT  0 8.592 0.084 8.616 ;
    END
  END o[225]
  PIN o[226]
    DIRECTION OUTPUT ;
    USE SIGNAL ;
    PORT
      LAYER M4 ;
        RECT  0 8.688 0.084 8.712 ;
    END
  END o[226]
  PIN o[227]
    DIRECTION OUTPUT ;
    USE SIGNAL ;
    PORT
      LAYER M4 ;
        RECT  0 8.784 0.084 8.808 ;
    END
  END o[227]
  PIN o[228]
    DIRECTION OUTPUT ;
    USE SIGNAL ;
    PORT
      LAYER M4 ;
        RECT  0 8.88 0.084 8.904 ;
    END
  END o[228]
  PIN o[229]
    DIRECTION OUTPUT ;
    USE SIGNAL ;
    PORT
      LAYER M4 ;
        RECT  0 8.976 0.084 9 ;
    END
  END o[229]
  PIN o[22]
    DIRECTION OUTPUT ;
    USE SIGNAL ;
    PORT
      LAYER M4 ;
        RECT  0 20.592 0.084 20.616 ;
    END
  END o[22]
  PIN o[230]
    DIRECTION OUTPUT ;
    USE SIGNAL ;
    PORT
      LAYER M4 ;
        RECT  0 9.072 0.084 9.096 ;
    END
  END o[230]
  PIN o[231]
    DIRECTION OUTPUT ;
    USE SIGNAL ;
    PORT
      LAYER M4 ;
        RECT  0 9.168 0.084 9.192 ;
    END
  END o[231]
  PIN o[232]
    DIRECTION OUTPUT ;
    USE SIGNAL ;
    PORT
      LAYER M4 ;
        RECT  0 9.264 0.084 9.288 ;
    END
  END o[232]
  PIN o[233]
    DIRECTION OUTPUT ;
    USE SIGNAL ;
    PORT
      LAYER M4 ;
        RECT  0 9.36 0.084 9.384 ;
    END
  END o[233]
  PIN o[234]
    DIRECTION OUTPUT ;
    USE SIGNAL ;
    PORT
      LAYER M4 ;
        RECT  0 9.456 0.084 9.48 ;
    END
  END o[234]
  PIN o[235]
    DIRECTION OUTPUT ;
    USE SIGNAL ;
    PORT
      LAYER M4 ;
        RECT  0 9.552 0.084 9.576 ;
    END
  END o[235]
  PIN o[236]
    DIRECTION OUTPUT ;
    USE SIGNAL ;
    PORT
      LAYER M4 ;
        RECT  0 9.648 0.084 9.672 ;
    END
  END o[236]
  PIN o[237]
    DIRECTION OUTPUT ;
    USE SIGNAL ;
    PORT
      LAYER M4 ;
        RECT  0 9.744 0.084 9.768 ;
    END
  END o[237]
  PIN o[238]
    DIRECTION OUTPUT ;
    USE SIGNAL ;
    PORT
      LAYER M4 ;
        RECT  0 9.84 0.084 9.864 ;
    END
  END o[238]
  PIN o[239]
    DIRECTION OUTPUT ;
    USE SIGNAL ;
    PORT
      LAYER M4 ;
        RECT  0 9.936 0.084 9.96 ;
    END
  END o[239]
  PIN o[23]
    DIRECTION OUTPUT ;
    USE SIGNAL ;
    PORT
      LAYER M4 ;
        RECT  0 20.688 0.084 20.712 ;
    END
  END o[23]
  PIN o[240]
    DIRECTION OUTPUT ;
    USE SIGNAL ;
    PORT
      LAYER M4 ;
        RECT  0 10.032 0.084 10.056 ;
    END
  END o[240]
  PIN o[241]
    DIRECTION OUTPUT ;
    USE SIGNAL ;
    PORT
      LAYER M4 ;
        RECT  0 10.128 0.084 10.152 ;
    END
  END o[241]
  PIN o[242]
    DIRECTION OUTPUT ;
    USE SIGNAL ;
    PORT
      LAYER M4 ;
        RECT  0 10.224 0.084 10.248 ;
    END
  END o[242]
  PIN o[243]
    DIRECTION OUTPUT ;
    USE SIGNAL ;
    PORT
      LAYER M4 ;
        RECT  0 10.32 0.084 10.344 ;
    END
  END o[243]
  PIN o[244]
    DIRECTION OUTPUT ;
    USE SIGNAL ;
    PORT
      LAYER M4 ;
        RECT  0 10.416 0.084 10.44 ;
    END
  END o[244]
  PIN o[245]
    DIRECTION OUTPUT ;
    USE SIGNAL ;
    PORT
      LAYER M4 ;
        RECT  0 10.512 0.084 10.536 ;
    END
  END o[245]
  PIN o[246]
    DIRECTION OUTPUT ;
    USE SIGNAL ;
    PORT
      LAYER M4 ;
        RECT  0 10.608 0.084 10.632 ;
    END
  END o[246]
  PIN o[247]
    DIRECTION OUTPUT ;
    USE SIGNAL ;
    PORT
      LAYER M4 ;
        RECT  0 10.704 0.084 10.728 ;
    END
  END o[247]
  PIN o[248]
    DIRECTION OUTPUT ;
    USE SIGNAL ;
    PORT
      LAYER M4 ;
        RECT  0 10.8 0.084 10.824 ;
    END
  END o[248]
  PIN o[249]
    DIRECTION OUTPUT ;
    USE SIGNAL ;
    PORT
      LAYER M4 ;
        RECT  0 10.896 0.084 10.92 ;
    END
  END o[249]
  PIN o[24]
    DIRECTION OUTPUT ;
    USE SIGNAL ;
    PORT
      LAYER M4 ;
        RECT  0 20.784 0.084 20.808 ;
    END
  END o[24]
  PIN o[250]
    DIRECTION OUTPUT ;
    USE SIGNAL ;
    PORT
      LAYER M4 ;
        RECT  0 10.992 0.084 11.016 ;
    END
  END o[250]
  PIN o[251]
    DIRECTION OUTPUT ;
    USE SIGNAL ;
    PORT
      LAYER M4 ;
        RECT  0 11.088 0.084 11.112 ;
    END
  END o[251]
  PIN o[252]
    DIRECTION OUTPUT ;
    USE SIGNAL ;
    PORT
      LAYER M4 ;
        RECT  0 11.184 0.084 11.208 ;
    END
  END o[252]
  PIN o[253]
    DIRECTION OUTPUT ;
    USE SIGNAL ;
    PORT
      LAYER M4 ;
        RECT  0 11.28 0.084 11.304 ;
    END
  END o[253]
  PIN o[254]
    DIRECTION OUTPUT ;
    USE SIGNAL ;
    PORT
      LAYER M4 ;
        RECT  0 11.376 0.084 11.4 ;
    END
  END o[254]
  PIN o[255]
    DIRECTION OUTPUT ;
    USE SIGNAL ;
    PORT
      LAYER M4 ;
        RECT  0 11.472 0.084 11.496 ;
    END
  END o[255]
  PIN o[256]
    DIRECTION OUTPUT ;
    USE SIGNAL ;
    PORT
      LAYER M4 ;
        RECT  0 11.568 0.084 11.592 ;
    END
  END o[256]
  PIN o[257]
    DIRECTION OUTPUT ;
    USE SIGNAL ;
    PORT
      LAYER M4 ;
        RECT  0 11.664 0.084 11.688 ;
    END
  END o[257]
  PIN o[258]
    DIRECTION OUTPUT ;
    USE SIGNAL ;
    PORT
      LAYER M4 ;
        RECT  0 11.76 0.084 11.784 ;
    END
  END o[258]
  PIN o[259]
    DIRECTION OUTPUT ;
    USE SIGNAL ;
    PORT
      LAYER M4 ;
        RECT  0 11.856 0.084 11.88 ;
    END
  END o[259]
  PIN o[25]
    DIRECTION OUTPUT ;
    USE SIGNAL ;
    PORT
      LAYER M4 ;
        RECT  0 20.88 0.084 20.904 ;
    END
  END o[25]
  PIN o[260]
    DIRECTION OUTPUT ;
    USE SIGNAL ;
    PORT
      LAYER M4 ;
        RECT  0 11.952 0.084 11.976 ;
    END
  END o[260]
  PIN o[261]
    DIRECTION OUTPUT ;
    USE SIGNAL ;
    PORT
      LAYER M4 ;
        RECT  0 12.048 0.084 12.072 ;
    END
  END o[261]
  PIN o[262]
    DIRECTION OUTPUT ;
    USE SIGNAL ;
    PORT
      LAYER M4 ;
        RECT  0 12.144 0.084 12.168 ;
    END
  END o[262]
  PIN o[263]
    DIRECTION OUTPUT ;
    USE SIGNAL ;
    PORT
      LAYER M4 ;
        RECT  0 12.24 0.084 12.264 ;
    END
  END o[263]
  PIN o[264]
    DIRECTION OUTPUT ;
    USE SIGNAL ;
    PORT
      LAYER M4 ;
        RECT  0 12.336 0.084 12.36 ;
    END
  END o[264]
  PIN o[265]
    DIRECTION OUTPUT ;
    USE SIGNAL ;
    PORT
      LAYER M4 ;
        RECT  0 12.432 0.084 12.456 ;
    END
  END o[265]
  PIN o[266]
    DIRECTION OUTPUT ;
    USE SIGNAL ;
    PORT
      LAYER M4 ;
        RECT  0 12.528 0.084 12.552 ;
    END
  END o[266]
  PIN o[267]
    DIRECTION OUTPUT ;
    USE SIGNAL ;
    PORT
      LAYER M4 ;
        RECT  0 12.624 0.084 12.648 ;
    END
  END o[267]
  PIN o[268]
    DIRECTION OUTPUT ;
    USE SIGNAL ;
    PORT
      LAYER M4 ;
        RECT  0 12.72 0.084 12.744 ;
    END
  END o[268]
  PIN o[269]
    DIRECTION OUTPUT ;
    USE SIGNAL ;
    PORT
      LAYER M4 ;
        RECT  0 12.816 0.084 12.84 ;
    END
  END o[269]
  PIN o[26]
    DIRECTION OUTPUT ;
    USE SIGNAL ;
    PORT
      LAYER M4 ;
        RECT  0 20.976 0.084 21 ;
    END
  END o[26]
  PIN o[270]
    DIRECTION OUTPUT ;
    USE SIGNAL ;
    PORT
      LAYER M4 ;
        RECT  0 12.912 0.084 12.936 ;
    END
  END o[270]
  PIN o[271]
    DIRECTION OUTPUT ;
    USE SIGNAL ;
    PORT
      LAYER M4 ;
        RECT  0 13.008 0.084 13.032 ;
    END
  END o[271]
  PIN o[272]
    DIRECTION OUTPUT ;
    USE SIGNAL ;
    PORT
      LAYER M4 ;
        RECT  0 13.104 0.084 13.128 ;
    END
  END o[272]
  PIN o[273]
    DIRECTION OUTPUT ;
    USE SIGNAL ;
    PORT
      LAYER M4 ;
        RECT  0 13.2 0.084 13.224 ;
    END
  END o[273]
  PIN o[274]
    DIRECTION OUTPUT ;
    USE SIGNAL ;
    PORT
      LAYER M4 ;
        RECT  0 13.296 0.084 13.32 ;
    END
  END o[274]
  PIN o[275]
    DIRECTION OUTPUT ;
    USE SIGNAL ;
    PORT
      LAYER M4 ;
        RECT  0 13.392 0.084 13.416 ;
    END
  END o[275]
  PIN o[276]
    DIRECTION OUTPUT ;
    USE SIGNAL ;
    PORT
      LAYER M4 ;
        RECT  0 13.488 0.084 13.512 ;
    END
  END o[276]
  PIN o[277]
    DIRECTION OUTPUT ;
    USE SIGNAL ;
    PORT
      LAYER M4 ;
        RECT  0 13.584 0.084 13.608 ;
    END
  END o[277]
  PIN o[278]
    DIRECTION OUTPUT ;
    USE SIGNAL ;
    PORT
      LAYER M4 ;
        RECT  0 13.68 0.084 13.704 ;
    END
  END o[278]
  PIN o[279]
    DIRECTION OUTPUT ;
    USE SIGNAL ;
    PORT
      LAYER M4 ;
        RECT  0 13.776 0.084 13.8 ;
    END
  END o[279]
  PIN o[27]
    DIRECTION OUTPUT ;
    USE SIGNAL ;
    PORT
      LAYER M4 ;
        RECT  0 21.072 0.084 21.096 ;
    END
  END o[27]
  PIN o[280]
    DIRECTION OUTPUT ;
    USE SIGNAL ;
    PORT
      LAYER M4 ;
        RECT  0 13.872 0.084 13.896 ;
    END
  END o[280]
  PIN o[281]
    DIRECTION OUTPUT ;
    USE SIGNAL ;
    PORT
      LAYER M4 ;
        RECT  0 13.968 0.084 13.992 ;
    END
  END o[281]
  PIN o[282]
    DIRECTION OUTPUT ;
    USE SIGNAL ;
    PORT
      LAYER M4 ;
        RECT  0 14.064 0.084 14.088 ;
    END
  END o[282]
  PIN o[283]
    DIRECTION OUTPUT ;
    USE SIGNAL ;
    PORT
      LAYER M4 ;
        RECT  0 14.16 0.084 14.184 ;
    END
  END o[283]
  PIN o[284]
    DIRECTION OUTPUT ;
    USE SIGNAL ;
    PORT
      LAYER M4 ;
        RECT  0 14.256 0.084 14.28 ;
    END
  END o[284]
  PIN o[285]
    DIRECTION OUTPUT ;
    USE SIGNAL ;
    PORT
      LAYER M4 ;
        RECT  0 14.352 0.084 14.376 ;
    END
  END o[285]
  PIN o[286]
    DIRECTION OUTPUT ;
    USE SIGNAL ;
    PORT
      LAYER M4 ;
        RECT  0 14.448 0.084 14.472 ;
    END
  END o[286]
  PIN o[287]
    DIRECTION OUTPUT ;
    USE SIGNAL ;
    PORT
      LAYER M4 ;
        RECT  0 14.544 0.084 14.568 ;
    END
  END o[287]
  PIN o[288]
    DIRECTION OUTPUT ;
    USE SIGNAL ;
    PORT
      LAYER M4 ;
        RECT  0 3.792 0.084 3.816 ;
    END
  END o[288]
  PIN o[289]
    DIRECTION OUTPUT ;
    USE SIGNAL ;
    PORT
      LAYER M4 ;
        RECT  0 3.888 0.084 3.912 ;
    END
  END o[289]
  PIN o[28]
    DIRECTION OUTPUT ;
    USE SIGNAL ;
    PORT
      LAYER M4 ;
        RECT  0 21.168 0.084 21.192 ;
    END
  END o[28]
  PIN o[290]
    DIRECTION OUTPUT ;
    USE SIGNAL ;
    PORT
      LAYER M4 ;
        RECT  0 3.984 0.084 4.008 ;
    END
  END o[290]
  PIN o[291]
    DIRECTION OUTPUT ;
    USE SIGNAL ;
    PORT
      LAYER M4 ;
        RECT  0 4.08 0.084 4.104 ;
    END
  END o[291]
  PIN o[292]
    DIRECTION OUTPUT ;
    USE SIGNAL ;
    PORT
      LAYER M4 ;
        RECT  0 4.176 0.084 4.2 ;
    END
  END o[292]
  PIN o[293]
    DIRECTION OUTPUT ;
    USE SIGNAL ;
    PORT
      LAYER M4 ;
        RECT  0 4.272 0.084 4.296 ;
    END
  END o[293]
  PIN o[294]
    DIRECTION OUTPUT ;
    USE SIGNAL ;
    PORT
      LAYER M4 ;
        RECT  0 4.368 0.084 4.392 ;
    END
  END o[294]
  PIN o[295]
    DIRECTION OUTPUT ;
    USE SIGNAL ;
    PORT
      LAYER M4 ;
        RECT  0 4.464 0.084 4.488 ;
    END
  END o[295]
  PIN o[296]
    DIRECTION OUTPUT ;
    USE SIGNAL ;
    PORT
      LAYER M4 ;
        RECT  0 4.56 0.084 4.584 ;
    END
  END o[296]
  PIN o[297]
    DIRECTION OUTPUT ;
    USE SIGNAL ;
    PORT
      LAYER M4 ;
        RECT  0 4.656 0.084 4.68 ;
    END
  END o[297]
  PIN o[298]
    DIRECTION OUTPUT ;
    USE SIGNAL ;
    PORT
      LAYER M4 ;
        RECT  0 4.752 0.084 4.776 ;
    END
  END o[298]
  PIN o[299]
    DIRECTION OUTPUT ;
    USE SIGNAL ;
    PORT
      LAYER M4 ;
        RECT  0 4.848 0.084 4.872 ;
    END
  END o[299]
  PIN o[29]
    DIRECTION OUTPUT ;
    USE SIGNAL ;
    PORT
      LAYER M4 ;
        RECT  0 21.264 0.084 21.288 ;
    END
  END o[29]
  PIN o[2]
    DIRECTION OUTPUT ;
    USE SIGNAL ;
    PORT
      LAYER M4 ;
        RECT  0 18.672 0.084 18.696 ;
    END
  END o[2]
  PIN o[300]
    DIRECTION OUTPUT ;
    USE SIGNAL ;
    PORT
      LAYER M4 ;
        RECT  0 4.944 0.084 4.968 ;
    END
  END o[300]
  PIN o[301]
    DIRECTION OUTPUT ;
    USE SIGNAL ;
    PORT
      LAYER M4 ;
        RECT  0 5.04 0.084 5.064 ;
    END
  END o[301]
  PIN o[302]
    DIRECTION OUTPUT ;
    USE SIGNAL ;
    PORT
      LAYER M4 ;
        RECT  0 5.136 0.084 5.16 ;
    END
  END o[302]
  PIN o[303]
    DIRECTION OUTPUT ;
    USE SIGNAL ;
    PORT
      LAYER M4 ;
        RECT  0 5.232 0.084 5.256 ;
    END
  END o[303]
  PIN o[30]
    DIRECTION OUTPUT ;
    USE SIGNAL ;
    PORT
      LAYER M4 ;
        RECT  0 21.36 0.084 21.384 ;
    END
  END o[30]
  PIN o[31]
    DIRECTION OUTPUT ;
    USE SIGNAL ;
    PORT
      LAYER M4 ;
        RECT  0 21.456 0.084 21.48 ;
    END
  END o[31]
  PIN o[32]
    DIRECTION OUTPUT ;
    USE SIGNAL ;
    PORT
      LAYER M4 ;
        RECT  0 27.696 0.084 27.72 ;
    END
  END o[32]
  PIN o[33]
    DIRECTION OUTPUT ;
    USE SIGNAL ;
    PORT
      LAYER M4 ;
        RECT  0 27.792 0.084 27.816 ;
    END
  END o[33]
  PIN o[34]
    DIRECTION OUTPUT ;
    USE SIGNAL ;
    PORT
      LAYER M4 ;
        RECT  0 27.888 0.084 27.912 ;
    END
  END o[34]
  PIN o[35]
    DIRECTION OUTPUT ;
    USE SIGNAL ;
    PORT
      LAYER M4 ;
        RECT  0 27.984 0.084 28.008 ;
    END
  END o[35]
  PIN o[36]
    DIRECTION OUTPUT ;
    USE SIGNAL ;
    PORT
      LAYER M4 ;
        RECT  0 28.08 0.084 28.104 ;
    END
  END o[36]
  PIN o[37]
    DIRECTION OUTPUT ;
    USE SIGNAL ;
    PORT
      LAYER M4 ;
        RECT  0 28.176 0.084 28.2 ;
    END
  END o[37]
  PIN o[38]
    DIRECTION OUTPUT ;
    USE SIGNAL ;
    PORT
      LAYER M4 ;
        RECT  0 28.272 0.084 28.296 ;
    END
  END o[38]
  PIN o[39]
    DIRECTION OUTPUT ;
    USE SIGNAL ;
    PORT
      LAYER M4 ;
        RECT  0 28.368 0.084 28.392 ;
    END
  END o[39]
  PIN o[3]
    DIRECTION OUTPUT ;
    USE SIGNAL ;
    PORT
      LAYER M4 ;
        RECT  0 18.768 0.084 18.792 ;
    END
  END o[3]
  PIN o[40]
    DIRECTION OUTPUT ;
    USE SIGNAL ;
    PORT
      LAYER M4 ;
        RECT  0 28.464 0.084 28.488 ;
    END
  END o[40]
  PIN o[41]
    DIRECTION OUTPUT ;
    USE SIGNAL ;
    PORT
      LAYER M4 ;
        RECT  0 28.56 0.084 28.584 ;
    END
  END o[41]
  PIN o[42]
    DIRECTION OUTPUT ;
    USE SIGNAL ;
    PORT
      LAYER M4 ;
        RECT  0 28.656 0.084 28.68 ;
    END
  END o[42]
  PIN o[43]
    DIRECTION OUTPUT ;
    USE SIGNAL ;
    PORT
      LAYER M4 ;
        RECT  0 28.752 0.084 28.776 ;
    END
  END o[43]
  PIN o[44]
    DIRECTION OUTPUT ;
    USE SIGNAL ;
    PORT
      LAYER M4 ;
        RECT  0 28.848 0.084 28.872 ;
    END
  END o[44]
  PIN o[45]
    DIRECTION OUTPUT ;
    USE SIGNAL ;
    PORT
      LAYER M4 ;
        RECT  0 28.944 0.084 28.968 ;
    END
  END o[45]
  PIN o[46]
    DIRECTION OUTPUT ;
    USE SIGNAL ;
    PORT
      LAYER M4 ;
        RECT  0 29.04 0.084 29.064 ;
    END
  END o[46]
  PIN o[47]
    DIRECTION OUTPUT ;
    USE SIGNAL ;
    PORT
      LAYER M4 ;
        RECT  0 29.136 0.084 29.16 ;
    END
  END o[47]
  PIN o[48]
    DIRECTION OUTPUT ;
    USE SIGNAL ;
    PORT
      LAYER M4 ;
        RECT  0 29.232 0.084 29.256 ;
    END
  END o[48]
  PIN o[49]
    DIRECTION OUTPUT ;
    USE SIGNAL ;
    PORT
      LAYER M4 ;
        RECT  0 29.328 0.084 29.352 ;
    END
  END o[49]
  PIN o[4]
    DIRECTION OUTPUT ;
    USE SIGNAL ;
    PORT
      LAYER M4 ;
        RECT  0 18.864 0.084 18.888 ;
    END
  END o[4]
  PIN o[50]
    DIRECTION OUTPUT ;
    USE SIGNAL ;
    PORT
      LAYER M4 ;
        RECT  0 29.424 0.084 29.448 ;
    END
  END o[50]
  PIN o[51]
    DIRECTION OUTPUT ;
    USE SIGNAL ;
    PORT
      LAYER M4 ;
        RECT  0 29.52 0.084 29.544 ;
    END
  END o[51]
  PIN o[52]
    DIRECTION OUTPUT ;
    USE SIGNAL ;
    PORT
      LAYER M4 ;
        RECT  0 29.616 0.084 29.64 ;
    END
  END o[52]
  PIN o[53]
    DIRECTION OUTPUT ;
    USE SIGNAL ;
    PORT
      LAYER M4 ;
        RECT  0 29.712 0.084 29.736 ;
    END
  END o[53]
  PIN o[54]
    DIRECTION OUTPUT ;
    USE SIGNAL ;
    PORT
      LAYER M4 ;
        RECT  0 29.808 0.084 29.832 ;
    END
  END o[54]
  PIN o[55]
    DIRECTION OUTPUT ;
    USE SIGNAL ;
    PORT
      LAYER M4 ;
        RECT  0 29.904 0.084 29.928 ;
    END
  END o[55]
  PIN o[56]
    DIRECTION OUTPUT ;
    USE SIGNAL ;
    PORT
      LAYER M4 ;
        RECT  0 30 0.084 30.024 ;
    END
  END o[56]
  PIN o[57]
    DIRECTION OUTPUT ;
    USE SIGNAL ;
    PORT
      LAYER M4 ;
        RECT  0 30.096 0.084 30.12 ;
    END
  END o[57]
  PIN o[58]
    DIRECTION OUTPUT ;
    USE SIGNAL ;
    PORT
      LAYER M4 ;
        RECT  0 30.192 0.084 30.216 ;
    END
  END o[58]
  PIN o[59]
    DIRECTION OUTPUT ;
    USE SIGNAL ;
    PORT
      LAYER M4 ;
        RECT  0 30.288 0.084 30.312 ;
    END
  END o[59]
  PIN o[5]
    DIRECTION OUTPUT ;
    USE SIGNAL ;
    PORT
      LAYER M4 ;
        RECT  0 18.96 0.084 18.984 ;
    END
  END o[5]
  PIN o[60]
    DIRECTION OUTPUT ;
    USE SIGNAL ;
    PORT
      LAYER M4 ;
        RECT  0 30.384 0.084 30.408 ;
    END
  END o[60]
  PIN o[61]
    DIRECTION OUTPUT ;
    USE SIGNAL ;
    PORT
      LAYER M4 ;
        RECT  0 30.48 0.084 30.504 ;
    END
  END o[61]
  PIN o[62]
    DIRECTION OUTPUT ;
    USE SIGNAL ;
    PORT
      LAYER M4 ;
        RECT  0 30.576 0.084 30.6 ;
    END
  END o[62]
  PIN o[63]
    DIRECTION OUTPUT ;
    USE SIGNAL ;
    PORT
      LAYER M4 ;
        RECT  0 30.672 0.084 30.696 ;
    END
  END o[63]
  PIN o[64]
    DIRECTION OUTPUT ;
    USE SIGNAL ;
    PORT
      LAYER M4 ;
        RECT  0 30.768 0.084 30.792 ;
    END
  END o[64]
  PIN o[65]
    DIRECTION OUTPUT ;
    USE SIGNAL ;
    PORT
      LAYER M4 ;
        RECT  0 30.864 0.084 30.888 ;
    END
  END o[65]
  PIN o[66]
    DIRECTION OUTPUT ;
    USE SIGNAL ;
    PORT
      LAYER M4 ;
        RECT  0 30.96 0.084 30.984 ;
    END
  END o[66]
  PIN o[67]
    DIRECTION OUTPUT ;
    USE SIGNAL ;
    PORT
      LAYER M4 ;
        RECT  0 31.056 0.084 31.08 ;
    END
  END o[67]
  PIN o[68]
    DIRECTION OUTPUT ;
    USE SIGNAL ;
    PORT
      LAYER M4 ;
        RECT  0 31.152 0.084 31.176 ;
    END
  END o[68]
  PIN o[69]
    DIRECTION OUTPUT ;
    USE SIGNAL ;
    PORT
      LAYER M4 ;
        RECT  0 31.248 0.084 31.272 ;
    END
  END o[69]
  PIN o[6]
    DIRECTION OUTPUT ;
    USE SIGNAL ;
    PORT
      LAYER M4 ;
        RECT  0 19.056 0.084 19.08 ;
    END
  END o[6]
  PIN o[70]
    DIRECTION OUTPUT ;
    USE SIGNAL ;
    PORT
      LAYER M4 ;
        RECT  0 31.344 0.084 31.368 ;
    END
  END o[70]
  PIN o[71]
    DIRECTION OUTPUT ;
    USE SIGNAL ;
    PORT
      LAYER M4 ;
        RECT  0 31.44 0.084 31.464 ;
    END
  END o[71]
  PIN o[72]
    DIRECTION OUTPUT ;
    USE SIGNAL ;
    PORT
      LAYER M4 ;
        RECT  0 31.536 0.084 31.56 ;
    END
  END o[72]
  PIN o[73]
    DIRECTION OUTPUT ;
    USE SIGNAL ;
    PORT
      LAYER M4 ;
        RECT  0 31.632 0.084 31.656 ;
    END
  END o[73]
  PIN o[74]
    DIRECTION OUTPUT ;
    USE SIGNAL ;
    PORT
      LAYER M4 ;
        RECT  0 31.728 0.084 31.752 ;
    END
  END o[74]
  PIN o[75]
    DIRECTION OUTPUT ;
    USE SIGNAL ;
    PORT
      LAYER M4 ;
        RECT  0 31.824 0.084 31.848 ;
    END
  END o[75]
  PIN o[76]
    DIRECTION OUTPUT ;
    USE SIGNAL ;
    PORT
      LAYER M4 ;
        RECT  0 31.92 0.084 31.944 ;
    END
  END o[76]
  PIN o[77]
    DIRECTION OUTPUT ;
    USE SIGNAL ;
    PORT
      LAYER M4 ;
        RECT  0 32.016 0.084 32.04 ;
    END
  END o[77]
  PIN o[78]
    DIRECTION OUTPUT ;
    USE SIGNAL ;
    PORT
      LAYER M4 ;
        RECT  0 32.112 0.084 32.136 ;
    END
  END o[78]
  PIN o[79]
    DIRECTION OUTPUT ;
    USE SIGNAL ;
    PORT
      LAYER M4 ;
        RECT  0 32.208 0.084 32.232 ;
    END
  END o[79]
  PIN o[7]
    DIRECTION OUTPUT ;
    USE SIGNAL ;
    PORT
      LAYER M4 ;
        RECT  0 19.152 0.084 19.176 ;
    END
  END o[7]
  PIN o[80]
    DIRECTION OUTPUT ;
    USE SIGNAL ;
    PORT
      LAYER M4 ;
        RECT  0 32.304 0.084 32.328 ;
    END
  END o[80]
  PIN o[81]
    DIRECTION OUTPUT ;
    USE SIGNAL ;
    PORT
      LAYER M4 ;
        RECT  0 32.4 0.084 32.424 ;
    END
  END o[81]
  PIN o[82]
    DIRECTION OUTPUT ;
    USE SIGNAL ;
    PORT
      LAYER M4 ;
        RECT  0 32.496 0.084 32.52 ;
    END
  END o[82]
  PIN o[83]
    DIRECTION OUTPUT ;
    USE SIGNAL ;
    PORT
      LAYER M4 ;
        RECT  0 32.592 0.084 32.616 ;
    END
  END o[83]
  PIN o[84]
    DIRECTION OUTPUT ;
    USE SIGNAL ;
    PORT
      LAYER M4 ;
        RECT  0 32.688 0.084 32.712 ;
    END
  END o[84]
  PIN o[85]
    DIRECTION OUTPUT ;
    USE SIGNAL ;
    PORT
      LAYER M4 ;
        RECT  0 32.784 0.084 32.808 ;
    END
  END o[85]
  PIN o[86]
    DIRECTION OUTPUT ;
    USE SIGNAL ;
    PORT
      LAYER M4 ;
        RECT  0 32.88 0.084 32.904 ;
    END
  END o[86]
  PIN o[87]
    DIRECTION OUTPUT ;
    USE SIGNAL ;
    PORT
      LAYER M4 ;
        RECT  0 32.976 0.084 33 ;
    END
  END o[87]
  PIN o[88]
    DIRECTION OUTPUT ;
    USE SIGNAL ;
    PORT
      LAYER M4 ;
        RECT  0 33.072 0.084 33.096 ;
    END
  END o[88]
  PIN o[89]
    DIRECTION OUTPUT ;
    USE SIGNAL ;
    PORT
      LAYER M4 ;
        RECT  0 33.168 0.084 33.192 ;
    END
  END o[89]
  PIN o[8]
    DIRECTION OUTPUT ;
    USE SIGNAL ;
    PORT
      LAYER M4 ;
        RECT  0 19.248 0.084 19.272 ;
    END
  END o[8]
  PIN o[90]
    DIRECTION OUTPUT ;
    USE SIGNAL ;
    PORT
      LAYER M4 ;
        RECT  0 33.264 0.084 33.288 ;
    END
  END o[90]
  PIN o[91]
    DIRECTION OUTPUT ;
    USE SIGNAL ;
    PORT
      LAYER M4 ;
        RECT  0 33.36 0.084 33.384 ;
    END
  END o[91]
  PIN o[92]
    DIRECTION OUTPUT ;
    USE SIGNAL ;
    PORT
      LAYER M4 ;
        RECT  0 33.456 0.084 33.48 ;
    END
  END o[92]
  PIN o[93]
    DIRECTION OUTPUT ;
    USE SIGNAL ;
    PORT
      LAYER M4 ;
        RECT  0 33.552 0.084 33.576 ;
    END
  END o[93]
  PIN o[94]
    DIRECTION OUTPUT ;
    USE SIGNAL ;
    PORT
      LAYER M4 ;
        RECT  0 33.648 0.084 33.672 ;
    END
  END o[94]
  PIN o[95]
    DIRECTION OUTPUT ;
    USE SIGNAL ;
    PORT
      LAYER M4 ;
        RECT  0 33.744 0.084 33.768 ;
    END
  END o[95]
  PIN o[96]
    DIRECTION OUTPUT ;
    USE SIGNAL ;
    PORT
      LAYER M4 ;
        RECT  0 21.552 0.084 21.576 ;
    END
  END o[96]
  PIN o[97]
    DIRECTION OUTPUT ;
    USE SIGNAL ;
    PORT
      LAYER M4 ;
        RECT  0 21.648 0.084 21.672 ;
    END
  END o[97]
  PIN o[98]
    DIRECTION OUTPUT ;
    USE SIGNAL ;
    PORT
      LAYER M4 ;
        RECT  0 21.744 0.084 21.768 ;
    END
  END o[98]
  PIN o[99]
    DIRECTION OUTPUT ;
    USE SIGNAL ;
    PORT
      LAYER M4 ;
        RECT  0 21.84 0.084 21.864 ;
    END
  END o[99]
  PIN o[9]
    DIRECTION OUTPUT ;
    USE SIGNAL ;
    PORT
      LAYER M4 ;
        RECT  0 19.344 0.084 19.368 ;
    END
  END o[9]
  PIN rfi
    DIRECTION INPUT ;
    USE SIGNAL ;
    PORT
      LAYER M4 ;
        RECT  21.516 30.672 21.6 30.696 ;
    END
  END rfi
  PIN rfo
    DIRECTION OUTPUT ;
    USE SIGNAL ;
    PORT
      LAYER M4 ;
        RECT  0 5.328 0.084 5.352 ;
    END
  END rfo
  PIN rs
    DIRECTION INPUT ;
    USE SIGNAL ;
    PORT
      LAYER M5 ;
        RECT  12.912 0 12.936 0.084 ;
    END
  END rs
  PIN VDD
    DIRECTION INOUT ;
    USE POWER ;
    PORT
      LAYER M5 ;
        RECT  18.792 2.151 18.912 32.409 ;
        RECT  16.092 2.151 16.212 32.409 ;
        RECT  13.392 2.151 13.512 32.409 ;
        RECT  10.692 2.151 10.812 32.409 ;
        RECT  7.992 2.151 8.112 32.409 ;
        RECT  5.292 2.151 5.412 32.409 ;
        RECT  2.592 2.151 2.712 32.409 ;
    END
  END VDD
  PIN VSS
    DIRECTION INOUT ;
    USE GROUND ;
    PORT
      LAYER M5 ;
        RECT  18.6 2.137 18.72 32.423 ;
        RECT  15.9 2.137 16.02 32.423 ;
        RECT  13.2 2.137 13.32 32.423 ;
        RECT  10.5 2.137 10.62 32.423 ;
        RECT  7.8 2.137 7.92 32.423 ;
        RECT  5.1 2.137 5.22 32.423 ;
        RECT  2.4 2.137 2.52 32.423 ;
    END
  END VSS
  OBS
    LAYER RVTN ;
     RECT  2.16 2.16 19.44 2.295 ;
     RECT  2.16 2.565 19.44 2.835 ;
     RECT  2.16 3.105 19.44 3.375 ;
     RECT  2.16 3.645 19.44 3.915 ;
     RECT  2.16 4.185 19.44 4.455 ;
     RECT  2.16 4.725 19.44 4.995 ;
     RECT  2.16 5.265 19.44 5.535 ;
     RECT  2.16 5.805 19.44 6.075 ;
     RECT  2.16 6.345 19.44 6.615 ;
     RECT  2.16 6.885 19.44 7.155 ;
     RECT  2.16 7.425 19.44 7.695 ;
     RECT  2.16 7.965 19.44 8.235 ;
     RECT  2.16 8.505 19.44 8.775 ;
     RECT  2.16 9.045 19.44 9.315 ;
     RECT  2.16 9.585 19.44 9.855 ;
     RECT  2.16 10.125 19.44 10.395 ;
     RECT  2.16 10.665 19.44 10.935 ;
     RECT  2.16 11.205 19.44 11.475 ;
     RECT  2.16 11.745 19.44 12.015 ;
     RECT  2.16 12.285 19.44 12.555 ;
     RECT  2.16 12.825 19.44 13.095 ;
     RECT  2.16 13.365 19.44 13.635 ;
     RECT  2.16 13.905 19.44 14.175 ;
     RECT  2.16 14.445 19.44 14.715 ;
     RECT  2.16 14.985 19.44 15.255 ;
     RECT  2.16 15.525 19.44 15.795 ;
     RECT  2.16 16.065 19.44 16.335 ;
     RECT  2.16 16.605 19.44 16.875 ;
     RECT  2.16 17.145 19.44 17.415 ;
     RECT  2.16 17.685 19.44 17.955 ;
     RECT  2.16 18.225 19.44 18.495 ;
     RECT  2.16 18.765 19.44 19.035 ;
     RECT  2.16 19.305 19.44 19.575 ;
     RECT  2.16 19.845 19.44 20.115 ;
     RECT  2.16 20.385 19.44 20.655 ;
     RECT  2.16 20.925 19.44 21.195 ;
     RECT  2.16 21.465 19.44 21.735 ;
     RECT  2.16 22.005 19.44 22.275 ;
     RECT  2.16 22.545 19.44 22.815 ;
     RECT  2.16 23.085 19.44 23.355 ;
     RECT  2.16 23.625 19.44 23.895 ;
     RECT  2.16 24.165 19.44 24.435 ;
     RECT  2.16 24.705 19.44 24.975 ;
     RECT  2.16 25.245 19.44 25.515 ;
     RECT  2.16 25.785 19.44 26.055 ;
     RECT  2.16 26.325 19.44 26.595 ;
     RECT  2.16 26.865 19.44 27.135 ;
     RECT  2.16 27.405 19.44 27.675 ;
     RECT  2.16 27.945 19.44 28.215 ;
     RECT  2.16 28.485 19.44 28.755 ;
     RECT  2.16 29.025 19.44 29.295 ;
     RECT  2.16 29.565 19.44 29.835 ;
     RECT  2.16 30.105 19.44 30.375 ;
     RECT  2.16 30.645 19.44 30.915 ;
     RECT  2.16 31.185 19.44 31.455 ;
     RECT  2.16 31.725 19.44 31.995 ;
     RECT  2.16 32.265 19.44 32.4 ;
    LAYER RVTP ;
     RECT  2.16 2.295 19.44 2.565 ;
     RECT  2.16 2.835 19.44 3.105 ;
     RECT  2.16 3.375 19.44 3.645 ;
     RECT  2.16 3.915 19.44 4.185 ;
     RECT  2.16 4.455 19.44 4.725 ;
     RECT  2.16 4.995 19.44 5.265 ;
     RECT  2.16 5.535 19.44 5.805 ;
     RECT  2.16 6.075 19.44 6.345 ;
     RECT  2.16 6.615 19.44 6.885 ;
     RECT  2.16 7.155 19.44 7.425 ;
     RECT  2.16 7.695 19.44 7.965 ;
     RECT  2.16 8.235 19.44 8.505 ;
     RECT  2.16 8.775 19.44 9.045 ;
     RECT  2.16 9.315 19.44 9.585 ;
     RECT  2.16 9.855 19.44 10.125 ;
     RECT  2.16 10.395 19.44 10.665 ;
     RECT  2.16 10.935 19.44 11.205 ;
     RECT  2.16 11.475 19.44 11.745 ;
     RECT  2.16 12.015 19.44 12.285 ;
     RECT  2.16 12.555 19.44 12.825 ;
     RECT  2.16 13.095 19.44 13.365 ;
     RECT  2.16 13.635 19.44 13.905 ;
     RECT  2.16 14.175 19.44 14.445 ;
     RECT  2.16 14.715 19.44 14.985 ;
     RECT  2.16 15.255 19.44 15.525 ;
     RECT  2.16 15.795 19.44 16.065 ;
     RECT  2.16 16.335 19.44 16.605 ;
     RECT  2.16 16.875 19.44 17.145 ;
     RECT  2.16 17.415 19.44 17.685 ;
     RECT  2.16 17.955 19.44 18.225 ;
     RECT  2.16 18.495 19.44 18.765 ;
     RECT  2.16 19.035 19.44 19.305 ;
     RECT  2.16 19.575 19.44 19.845 ;
     RECT  2.16 20.115 19.44 20.385 ;
     RECT  2.16 20.655 19.44 20.925 ;
     RECT  2.16 21.195 19.44 21.465 ;
     RECT  2.16 21.735 19.44 22.005 ;
     RECT  2.16 22.275 19.44 22.545 ;
     RECT  2.16 22.815 19.44 23.085 ;
     RECT  2.16 23.355 19.44 23.625 ;
     RECT  2.16 23.895 19.44 24.165 ;
     RECT  2.16 24.435 19.44 24.705 ;
     RECT  2.16 24.975 19.44 25.245 ;
     RECT  2.16 25.515 19.44 25.785 ;
     RECT  2.16 26.055 19.44 26.325 ;
     RECT  2.16 26.595 19.44 26.865 ;
     RECT  2.16 27.135 19.44 27.405 ;
     RECT  2.16 27.675 19.44 27.945 ;
     RECT  2.16 28.215 19.44 28.485 ;
     RECT  2.16 28.755 19.44 29.025 ;
     RECT  2.16 29.295 19.44 29.565 ;
     RECT  2.16 29.835 19.44 30.105 ;
     RECT  2.16 30.375 19.44 30.645 ;
     RECT  2.16 30.915 19.44 31.185 ;
     RECT  2.16 31.455 19.44 31.725 ;
     RECT  2.16 31.995 19.44 32.265 ;
    LAYER M1 ;
     RECT  2.16 2.151 19.44 32.409 ;
    LAYER M2 ;
     RECT  0.103 6.516 0.139 6.534 ;
     RECT  0.103 7.704 0.139 8.496 ;
     RECT  0.103 17.271 0.139 17.289 ;
     RECT  0.103 18.54 0.139 18.558 ;
     RECT  0.103 19.62 0.139 21.609 ;
     RECT  0.139 6.516 0.203 8.496 ;
     RECT  0.139 17.271 0.203 17.514 ;
     RECT  0.139 18.54 0.203 21.609 ;
     RECT  0.103 23.94 0.203 23.958 ;
     RECT  0.103 24.948 0.203 25.542 ;
     RECT  0.103 27.684 0.203 27.702 ;
     RECT  0.103 29.376 0.203 29.394 ;
     RECT  0.103 5.004 0.211 5.022 ;
     RECT  0.103 9.936 0.211 9.954 ;
     RECT  0.203 7.236 0.239 7.722 ;
     RECT  0.203 17.496 0.239 17.514 ;
     RECT  0.203 19.161 0.239 19.179 ;
     RECT  0.203 20.196 0.239 20.412 ;
     RECT  0.203 24.948 0.239 24.966 ;
     RECT  0.103 13.608 0.283 13.626 ;
     RECT  0.211 5.004 0.311 5.184 ;
     RECT  0.239 7.704 0.347 7.722 ;
     RECT  0.211 9.36 0.347 9.954 ;
     RECT  0.239 20.241 0.347 20.412 ;
     RECT  0.247 26.136 0.347 26.154 ;
     RECT  0.211 28.26 0.347 28.278 ;
     RECT  0.283 13.068 0.355 13.626 ;
     RECT  0.355 13.068 0.383 13.824 ;
     RECT  0.319 21.816 0.419 21.834 ;
     RECT  0.383 13.806 0.455 13.824 ;
     RECT  0.311 5.004 0.499 5.094 ;
     RECT  0.139 3.726 0.535 3.744 ;
     RECT  0.103 33.156 0.607 33.678 ;
     RECT  0.499 4.968 1.147 5.094 ;
     RECT  0.347 9.936 1.147 9.954 ;
     RECT  1.147 9.864 1.175 9.954 ;
     RECT  0.203 8.478 1.183 8.496 ;
     RECT  0.103 30.186 1.183 30.204 ;
     RECT  1.183 11.214 1.283 11.232 ;
     RECT  1.183 30.186 1.283 30.636 ;
     RECT  1.183 7.974 1.291 8.496 ;
     RECT  1.291 7.902 1.391 8.496 ;
     RECT  0.823 2.106 2.16 2.124 ;
     RECT  0.535 3.384 2.16 3.744 ;
     RECT  1.147 4.806 2.16 5.094 ;
     RECT  1.391 8.478 2.16 8.496 ;
     RECT  1.175 9.864 2.16 9.882 ;
     RECT  0.535 15.876 2.16 15.894 ;
     RECT  1.183 16.884 2.16 16.902 ;
     RECT  1.723 18.846 2.16 18.864 ;
     RECT  0.571 27.414 2.16 27.432 ;
     RECT  1.283 30.186 2.16 30.204 ;
     RECT  0.607 32.58 2.16 33.678 ;
     RECT  2.16 2.106 2.587 33.678 ;
     RECT  2.587 1.998 3.595 33.678 ;
     RECT  3.595 1.962 4.495 33.678 ;
     RECT  4.495 1.881 6.583 33.678 ;
     RECT  6.583 1.836 10.247 33.678 ;
     RECT  10.247 2.034 10.319 33.678 ;
     RECT  10.319 2.151 11.219 33.678 ;
     RECT  11.219 2.151 11.839 33.642 ;
     RECT  11.839 2.106 12.011 33.642 ;
     RECT  12.011 2.106 12.019 33.264 ;
     RECT  12.019 2.07 12.299 33.264 ;
     RECT  12.299 2.07 12.623 33.138 ;
     RECT  12.623 2.07 13.703 32.796 ;
     RECT  13.703 2.07 14.099 32.562 ;
     RECT  14.099 2.106 14.171 32.562 ;
     RECT  14.171 2.106 16.159 32.526 ;
     RECT  16.159 2.034 16.943 32.526 ;
     RECT  16.943 2.106 18.023 32.526 ;
     RECT  18.023 2.106 18.779 32.409 ;
     RECT  18.779 2.151 19.44 32.409 ;
     RECT  19.44 25.218 19.931 29.052 ;
     RECT  19.44 29.844 19.931 30.096 ;
     RECT  19.44 2.304 19.967 24.228 ;
     RECT  19.931 25.218 19.967 27.198 ;
     RECT  19.967 2.304 20.507 14.706 ;
     RECT  19.931 27.954 20.507 29.052 ;
     RECT  20.507 2.304 20.543 3.204 ;
     RECT  20.507 4.23 20.543 11.466 ;
     RECT  19.967 15.768 20.543 24.228 ;
     RECT  19.967 25.83 20.543 25.848 ;
     RECT  19.967 26.64 20.543 27.198 ;
     RECT  20.507 28.296 20.543 29.052 ;
     RECT  20.543 4.428 20.579 9.306 ;
     RECT  20.543 15.768 20.579 17.478 ;
     RECT  20.543 18.468 20.579 23.346 ;
     RECT  20.543 24.21 20.579 24.228 ;
     RECT  20.507 12.564 20.615 14.436 ;
     RECT  20.579 20.16 20.615 23.346 ;
     RECT  20.615 22.59 20.651 23.346 ;
     RECT  20.651 23.058 20.687 23.346 ;
     RECT  20.615 20.16 20.723 21.528 ;
     RECT  20.723 20.43 20.759 21.528 ;
     RECT  20.579 5.778 21.407 9.306 ;
     RECT  20.759 21.51 21.407 21.528 ;
     RECT  21.407 5.778 21.415 9.036 ;
     RECT  21.415 5.166 21.443 9.036 ;
     RECT  20.543 10.098 21.443 11.466 ;
     RECT  20.615 12.798 21.443 14.436 ;
     RECT  20.579 15.768 21.443 17.406 ;
     RECT  20.579 18.468 21.443 19.296 ;
     RECT  19.931 30.078 21.443 30.096 ;
     RECT  20.543 2.376 21.479 3.204 ;
     RECT  21.443 10.098 21.479 10.89 ;
     RECT  21.443 12.834 21.479 14.166 ;
     RECT  21.443 16.848 21.479 16.866 ;
     RECT  21.443 19.008 21.479 19.296 ;
     RECT  20.687 23.058 21.479 23.112 ;
     RECT  21.479 2.376 21.515 2.394 ;
     RECT  21.479 3.186 21.515 3.204 ;
     RECT  21.443 5.166 21.515 6.03 ;
     RECT  21.443 6.93 21.515 8.766 ;
     RECT  21.479 10.098 21.515 10.728 ;
     RECT  21.479 12.834 21.515 12.852 ;
     RECT  21.479 14.148 21.515 14.166 ;
     RECT  21.479 19.278 21.515 19.296 ;
     RECT  21.479 23.094 21.515 23.112 ;
     RECT  20.543 27.18 21.515 27.198 ;
     RECT  20.543 28.296 21.515 28.782 ;
     RECT  21.487 30.456 21.587 30.474 ;
    LAYER M3 ;
     RECT  21.492 0.811 21.51 0.907 ;
     RECT  20.52 1.099 20.538 1.195 ;
     RECT  21.42 0.907 21.51 1.675 ;
     RECT  16.704 0.715 16.722 1.723 ;
     RECT  17.604 1.387 17.622 1.723 ;
     RECT  16.704 1.723 17.622 1.915 ;
     RECT  6.588 1.831 6.606 1.957 ;
     RECT  7.524 1.876 7.542 1.957 ;
     RECT  2.664 1.915 2.682 1.993 ;
     RECT  6.588 1.957 7.542 1.993 ;
     RECT  16.704 1.915 18.162 2.011 ;
     RECT  10.224 1.831 10.242 2.029 ;
     RECT  12.132 1.819 12.15 2.059 ;
     RECT  12.996 1.771 13.158 2.059 ;
     RECT  3.6 1.957 3.618 2.065 ;
     RECT  4.5 1.876 4.518 2.065 ;
     RECT  12.132 2.059 13.158 2.065 ;
     RECT  9.036 2.011 9.054 2.101 ;
     RECT  10.224 2.029 10.314 2.101 ;
     RECT  12.024 2.065 13.158 2.101 ;
     RECT  16.092 2.011 18.162 2.101 ;
     RECT  19.296 2.011 19.314 2.101 ;
     RECT  2.592 1.993 2.682 2.143 ;
     RECT  3.6 2.065 4.518 2.143 ;
     RECT  5.868 1.993 7.542 2.143 ;
     RECT  9.036 2.101 10.314 2.143 ;
     RECT  11.844 2.101 13.158 2.143 ;
     RECT  16.092 2.101 19.314 2.143 ;
     RECT  20.196 1.195 20.538 2.155 ;
     RECT  21.384 1.675 21.51 2.155 ;
     RECT  11.844 2.143 13.305 2.191 ;
     RECT  14.076 2.065 14.094 2.191 ;
     RECT  2.415 2.143 2.682 2.227 ;
     RECT  11.7 2.191 13.305 2.227 ;
     RECT  14.076 2.191 14.994 2.227 ;
     RECT  3.6 2.143 7.905 2.263 ;
     RECT  20.196 2.155 21.51 2.285 ;
     RECT  15.915 2.143 19.314 2.299 ;
     RECT  20.196 2.285 20.538 2.327 ;
     RECT  9.036 2.143 10.605 2.335 ;
     RECT  11.7 2.227 14.994 2.335 ;
     RECT  15.732 2.299 19.314 2.347 ;
     RECT  20.196 2.327 20.502 2.347 ;
     RECT  2.34 2.227 2.682 2.371 ;
     RECT  3.42 2.263 7.905 2.371 ;
     RECT  11.376 2.335 14.994 2.395 ;
     RECT  15.732 2.347 20.502 2.395 ;
     RECT  2.34 2.371 7.905 2.413 ;
     RECT  8.892 2.335 10.605 2.413 ;
     RECT  11.376 2.395 20.502 2.413 ;
     RECT  8.892 2.413 20.502 2.489 ;
     RECT  19.908 2.489 20.502 2.669 ;
     RECT  2.34 2.413 8.097 2.731 ;
     RECT  8.892 2.489 19.098 2.731 ;
     RECT  2.34 2.731 19.098 2.803 ;
     RECT  2.304 2.803 19.098 2.861 ;
     RECT  20.412 2.669 20.502 2.861 ;
     RECT  20.484 2.861 20.502 3.101 ;
     RECT  21.276 2.285 21.51 3.209 ;
     RECT  21.276 3.209 21.366 3.341 ;
     RECT  0.828 2.101 0.846 3.379 ;
     RECT  21.312 3.341 21.366 3.389 ;
     RECT  2.34 2.861 19.098 3.451 ;
     RECT  21.312 3.389 21.33 3.629 ;
     RECT  2.34 3.451 19.314 3.643 ;
     RECT  0.54 3.379 0.846 3.691 ;
     RECT  0.108 3.691 0.846 3.821 ;
     RECT  20.196 3.787 20.214 3.883 ;
     RECT  20.196 3.883 20.502 3.979 ;
     RECT  0.144 3.821 0.846 4.171 ;
     RECT  20.16 3.979 20.502 4.225 ;
     RECT  20.16 4.225 20.538 4.423 ;
     RECT  20.16 4.423 20.574 4.523 ;
     RECT  0.144 4.171 1.17 4.651 ;
     RECT  1.98 3.643 19.314 4.651 ;
     RECT  0.144 4.651 19.314 4.781 ;
     RECT  1.98 4.781 19.314 4.877 ;
     RECT  0.144 4.781 1.242 4.999 ;
     RECT  0.108 4.999 1.242 5.099 ;
     RECT  21.42 4.267 21.438 5.131 ;
     RECT  0.108 5.099 1.17 5.261 ;
     RECT  20.52 4.523 20.574 5.323 ;
     RECT  20.484 5.323 20.574 5.453 ;
     RECT  0.216 5.261 1.17 5.501 ;
     RECT  20.484 5.453 20.538 5.531 ;
     RECT  1.98 4.877 19.098 5.755 ;
     RECT  0.216 5.501 0.846 5.933 ;
     RECT  21.42 5.131 21.51 6.035 ;
     RECT  20.52 5.531 20.538 6.283 ;
     RECT  21.42 6.035 21.474 6.283 ;
     RECT  1.98 5.755 19.314 6.317 ;
     RECT  0.144 6.331 0.198 6.511 ;
     RECT  20.52 6.283 21.474 6.683 ;
     RECT  21.204 6.683 21.474 6.763 ;
     RECT  0.108 6.511 0.198 6.797 ;
     RECT  1.98 6.317 19.242 7.037 ;
     RECT  0.144 6.797 0.198 7.051 ;
     RECT  0.144 7.051 0.378 7.181 ;
     RECT  21.204 6.763 21.51 7.421 ;
     RECT  0.144 7.181 0.342 7.627 ;
     RECT  21.24 7.421 21.51 7.691 ;
     RECT  2.304 7.037 19.242 7.771 ;
     RECT  1.296 7.867 1.314 7.897 ;
     RECT  1.296 7.897 1.386 7.915 ;
     RECT  1.188 7.915 1.386 7.949 ;
     RECT  1.188 7.949 1.314 7.997 ;
     RECT  0.108 7.627 0.342 8.473 ;
     RECT  20.412 8.395 20.43 8.501 ;
     RECT  21.348 7.691 21.51 8.539 ;
     RECT  0.108 8.473 0.558 8.621 ;
     RECT  0.144 8.621 0.558 8.717 ;
     RECT  21.276 8.539 21.51 8.771 ;
     RECT  20.52 8.587 20.538 8.779 ;
     RECT  21.276 8.771 21.438 8.779 ;
     RECT  20.52 8.779 21.438 8.909 ;
     RECT  2.304 7.771 19.314 8.971 ;
     RECT  20.52 8.909 20.574 9.113 ;
     RECT  20.52 9.113 20.538 9.355 ;
     RECT  20.412 9.355 20.538 9.383 ;
     RECT  20.412 9.383 20.43 9.451 ;
     RECT  20.196 9.451 20.43 9.581 ;
     RECT  1.98 8.971 19.314 9.629 ;
     RECT  21.384 8.909 21.438 9.835 ;
     RECT  0.144 8.717 0.342 9.931 ;
     RECT  1.152 9.859 1.17 9.931 ;
     RECT  21.384 9.835 21.51 10.027 ;
     RECT  0.108 9.931 1.17 10.253 ;
     RECT  1.98 9.629 19.278 10.363 ;
     RECT  20.196 9.581 20.214 10.733 ;
     RECT  21.312 10.027 21.51 10.733 ;
     RECT  0.144 10.253 1.17 10.829 ;
     RECT  21.312 10.733 21.474 10.829 ;
     RECT  21.42 10.829 21.474 10.895 ;
     RECT  0.216 10.829 1.17 11.179 ;
     RECT  0.216 11.179 1.206 11.209 ;
     RECT  1.98 10.363 19.314 11.209 ;
     RECT  0.216 11.209 19.314 11.261 ;
     RECT  0.216 11.261 0.558 11.405 ;
     RECT  21.42 10.895 21.438 11.471 ;
     RECT  21.312 11.563 21.33 11.693 ;
     RECT  1.98 11.261 19.314 11.851 ;
     RECT  1.98 11.851 19.386 11.981 ;
     RECT  0.216 11.405 0.378 11.995 ;
     RECT  20.52 11.245 20.538 12.043 ;
     RECT  1.98 11.981 19.314 12.077 ;
     RECT  20.484 12.043 20.538 12.083 ;
     RECT  2.088 12.077 19.314 12.557 ;
     RECT  20.592 12.235 20.61 12.587 ;
     RECT  2.196 12.557 19.314 12.797 ;
     RECT  21.42 12.427 21.438 12.829 ;
     RECT  21.42 12.829 21.51 13.133 ;
     RECT  0.144 11.995 0.378 13.579 ;
     RECT  0.108 13.579 0.378 13.801 ;
     RECT  1.152 13.675 1.17 13.801 ;
     RECT  0.108 13.801 1.17 13.853 ;
     RECT  0.108 13.853 0.306 13.901 ;
     RECT  1.152 13.853 1.17 13.949 ;
     RECT  2.268 12.797 19.314 14.099 ;
     RECT  21.42 13.133 21.474 14.143 ;
     RECT  20.484 13.867 20.502 14.215 ;
     RECT  20.484 14.215 20.538 14.381 ;
     RECT  21.42 14.143 21.51 14.477 ;
     RECT  0.108 13.901 0.234 14.669 ;
     RECT  20.484 14.381 20.502 14.711 ;
     RECT  0.108 14.669 0.198 14.717 ;
     RECT  0.18 14.717 0.198 14.765 ;
     RECT  2.268 14.099 19.17 14.875 ;
     RECT  2.268 14.875 19.314 15.025 ;
     RECT  21.42 14.477 21.474 15.115 ;
     RECT  21.312 15.115 21.474 15.245 ;
     RECT  2.268 15.025 19.962 15.341 ;
     RECT  0.36 15.403 0.378 15.547 ;
     RECT  0.252 15.547 0.378 15.691 ;
     RECT  2.268 15.341 19.314 15.719 ;
     RECT  0.252 15.691 0.45 15.739 ;
     RECT  21.312 15.245 21.438 15.787 ;
     RECT  0.144 15.739 0.45 15.871 ;
     RECT  0.144 15.871 0.558 15.917 ;
     RECT  21.276 15.787 21.438 15.979 ;
     RECT  2.268 15.719 19.17 15.989 ;
     RECT  2.268 15.989 19.098 16.025 ;
     RECT  0.18 15.917 0.558 16.075 ;
     RECT  0.18 16.075 0.666 16.171 ;
     RECT  21.276 15.979 21.474 16.303 ;
     RECT  21.24 16.303 21.474 16.375 ;
     RECT  20.52 16.375 21.474 16.397 ;
     RECT  0.18 16.171 1.17 16.493 ;
     RECT  21.276 16.397 21.474 16.601 ;
     RECT  2.268 16.025 19.026 16.771 ;
     RECT  1.152 16.493 1.17 16.795 ;
     RECT  21.348 16.601 21.474 16.843 ;
     RECT  1.152 16.795 1.242 16.973 ;
     RECT  1.152 16.973 1.206 17.021 ;
     RECT  2.268 16.771 19.17 17.035 ;
     RECT  1.188 17.021 1.206 17.117 ;
     RECT  2.268 17.035 19.242 17.131 ;
     RECT  0.18 16.493 0.342 17.227 ;
     RECT  0.108 17.227 0.342 17.294 ;
     RECT  20.52 16.397 20.538 17.323 ;
     RECT  0.144 17.294 0.342 17.453 ;
     RECT  20.52 17.323 20.574 17.483 ;
     RECT  0.144 17.453 0.234 17.519 ;
     RECT  2.268 17.131 19.35 17.653 ;
     RECT  20.52 17.483 20.538 17.753 ;
     RECT  21.348 16.843 21.51 17.837 ;
     RECT  1.152 17.947 1.17 17.995 ;
     RECT  2.268 17.653 19.386 17.995 ;
     RECT  0.144 17.519 0.162 18.379 ;
     RECT  0.108 18.379 0.162 18.427 ;
     RECT  0.108 18.427 0.198 18.563 ;
     RECT  0.144 18.563 0.198 18.955 ;
     RECT  1.152 17.995 19.386 18.989 ;
     RECT  21.384 17.837 21.51 19.051 ;
     RECT  0.144 18.955 0.342 19.085 ;
     RECT  0.144 19.085 0.234 19.184 ;
     RECT  1.152 18.989 1.278 19.277 ;
     RECT  21.312 19.051 21.51 19.301 ;
     RECT  21.312 19.301 21.402 19.373 ;
     RECT  0.144 19.184 0.198 19.615 ;
     RECT  20.52 18.769 20.538 19.885 ;
     RECT  0.108 19.615 0.198 20.011 ;
     RECT  20.52 19.885 20.574 20.155 ;
     RECT  21.384 19.373 21.402 20.155 ;
     RECT  0.108 20.011 0.342 20.347 ;
     RECT  1.152 20.059 1.17 20.347 ;
     RECT  1.152 20.347 1.278 20.381 ;
     RECT  20.52 20.155 21.402 20.429 ;
     RECT  1.26 20.381 1.278 20.477 ;
     RECT  0.108 20.347 0.414 20.525 ;
     RECT  2.268 18.989 19.386 21.259 ;
     RECT  20.556 20.429 21.402 21.259 ;
     RECT  2.268 21.259 21.402 21.533 ;
     RECT  0.108 20.525 0.198 21.614 ;
     RECT  0.324 21.643 0.342 21.787 ;
     RECT  0.324 21.787 0.414 21.839 ;
     RECT  0.324 21.839 0.342 21.869 ;
     RECT  2.268 21.533 20.682 22.013 ;
     RECT  21.42 21.739 21.438 22.397 ;
     RECT  20.016 22.013 20.682 22.541 ;
     RECT  0.144 22.411 0.162 22.603 ;
     RECT  2.268 22.013 19.278 22.783 ;
     RECT  0.144 22.603 0.234 23.035 ;
     RECT  21.456 23.053 21.474 23.089 ;
     RECT  0.144 23.035 0.27 23.213 ;
     RECT  0.144 23.213 0.234 23.645 ;
     RECT  0.144 23.645 0.198 23.935 ;
     RECT  2.268 22.783 19.314 23.995 ;
     RECT  0.108 23.935 0.198 24.077 ;
     RECT  2.268 23.995 19.35 24.359 ;
     RECT  21.456 23.089 21.51 24.379 ;
     RECT  0.18 24.077 0.198 24.523 ;
     RECT  20.52 22.541 20.682 24.715 ;
     RECT  21.456 24.379 21.582 24.715 ;
     RECT  0.18 24.523 0.342 24.907 ;
     RECT  0.108 24.907 0.342 25.099 ;
     RECT  2.268 24.359 19.314 25.147 ;
     RECT  20.52 24.715 21.582 25.147 ;
     RECT  2.268 25.147 21.582 25.229 ;
     RECT  21.312 25.229 21.582 25.325 ;
     RECT  2.268 25.229 20.574 25.517 ;
     RECT  0.108 25.099 0.45 25.547 ;
     RECT  0.18 25.547 0.45 25.771 ;
     RECT  0.18 25.771 0.702 25.819 ;
     RECT  0.18 25.819 1.17 26.107 ;
     RECT  2.268 25.517 20.538 26.189 ;
     RECT  0.18 26.107 1.278 26.237 ;
     RECT  0.18 26.237 0.594 26.587 ;
     RECT  2.268 26.189 19.422 26.599 ;
     RECT  20.52 26.189 20.538 26.669 ;
     RECT  21.564 25.325 21.582 27.175 ;
     RECT  0.144 26.587 0.594 27.355 ;
     RECT  0.144 27.355 1.17 27.437 ;
     RECT  2.196 26.599 19.422 27.499 ;
     RECT  0.144 27.437 0.342 27.679 ;
     RECT  21.492 27.175 21.582 27.739 ;
     RECT  2.196 27.499 19.926 27.743 ;
     RECT  21.384 27.739 21.582 27.787 ;
     RECT  0.108 27.679 0.342 27.821 ;
     RECT  21.276 27.787 21.582 27.917 ;
     RECT  14.976 27.743 19.386 27.941 ;
     RECT  15.012 27.941 19.386 28.013 ;
     RECT  0.144 27.821 0.342 28.219 ;
     RECT  15.012 28.013 19.314 28.247 ;
     RECT  20.484 27.949 20.502 28.397 ;
     RECT  0.144 28.219 0.414 28.493 ;
     RECT  15.084 28.247 19.314 28.843 ;
     RECT  15.084 28.843 19.386 29.069 ;
     RECT  21.492 27.917 21.582 29.131 ;
     RECT  0.144 28.493 0.162 29.227 ;
     RECT  20.52 29.029 20.538 29.227 ;
     RECT  20.412 29.227 20.538 29.261 ;
     RECT  0.108 29.227 0.162 29.275 ;
     RECT  0.108 29.275 0.198 29.399 ;
     RECT  20.412 29.261 20.43 29.453 ;
     RECT  1.152 27.437 1.17 29.707 ;
     RECT  15.408 29.069 19.386 29.707 ;
     RECT  15.408 29.707 19.926 29.867 ;
     RECT  1.152 29.707 1.422 29.885 ;
     RECT  21.42 29.131 21.582 30.101 ;
     RECT  0.108 29.399 0.162 30.209 ;
     RECT  15.408 29.867 19.314 30.371 ;
     RECT  15.408 30.371 19.278 30.379 ;
     RECT  0.324 30.283 0.342 30.413 ;
     RECT  2.196 27.743 14.166 30.451 ;
     RECT  14.904 30.379 19.278 30.451 ;
     RECT  21.492 30.101 21.582 30.479 ;
     RECT  21.492 30.479 21.51 30.509 ;
     RECT  1.152 29.885 1.35 30.653 ;
     RECT  2.196 30.451 19.278 30.859 ;
     RECT  1.728 30.859 19.278 31.181 ;
     RECT  0.576 30.763 0.63 31.339 ;
     RECT  0.108 31.339 0.63 31.387 ;
     RECT  1.728 31.181 17.262 31.387 ;
     RECT  18 31.181 19.278 31.531 ;
     RECT  18 31.531 19.314 31.709 ;
     RECT  0.108 31.387 17.262 31.721 ;
     RECT  15.084 31.721 17.262 31.805 ;
     RECT  15.084 31.805 16.326 31.829 ;
     RECT  17.064 31.805 17.262 31.829 ;
     RECT  15.084 31.829 16.197 31.919 ;
     RECT  18 31.709 19.098 31.955 ;
     RECT  15.915 31.919 16.197 32.147 ;
     RECT  18 31.955 18.897 32.147 ;
     RECT  0.108 31.721 14.166 32.261 ;
     RECT  0.108 32.261 5.205 32.297 ;
     RECT  17.064 31.829 17.082 32.297 ;
     RECT  6.3 32.261 14.166 32.333 ;
     RECT  0.108 32.297 3.15 32.369 ;
     RECT  0.108 32.369 3.114 32.417 ;
     RECT  3.924 32.297 5.205 32.417 ;
     RECT  6.66 32.333 14.166 32.417 ;
     RECT  15.915 32.147 16.005 32.417 ;
     RECT  18 32.147 18.705 32.417 ;
     RECT  3.096 32.417 3.114 32.459 ;
     RECT  6.66 32.417 12.618 32.459 ;
     RECT  3.924 32.417 4.41 32.495 ;
     RECT  3.924 32.495 4.374 32.531 ;
     RECT  18 32.417 18.018 32.531 ;
     RECT  3.924 32.531 3.942 32.567 ;
     RECT  13.68 32.417 14.166 32.567 ;
     RECT  6.732 32.459 12.618 32.603 ;
     RECT  6.732 32.603 10.242 32.669 ;
     RECT  13.68 32.567 13.698 32.801 ;
     RECT  6.732 32.669 8.298 32.813 ;
     RECT  9.072 32.669 10.242 32.909 ;
     RECT  9.144 32.909 10.242 33.005 ;
     RECT  10.98 32.603 12.618 33.143 ;
     RECT  0.108 32.417 2.322 33.224 ;
     RECT  10.98 33.143 12.294 33.224 ;
     RECT  1.8 33.224 2.322 33.269 ;
     RECT  11.196 33.224 12.294 33.269 ;
     RECT  6.732 32.813 6.858 33.293 ;
     RECT  1.8 33.269 1.818 33.341 ;
     RECT  9.468 33.005 10.242 33.341 ;
     RECT  0.108 33.224 0.666 33.377 ;
     RECT  9.828 33.341 10.242 33.377 ;
     RECT  7.956 32.813 8.298 33.485 ;
     RECT  6.84 33.293 6.858 33.494 ;
     RECT  11.196 33.269 12.006 33.494 ;
     RECT  0.108 33.377 0.594 33.647 ;
     RECT  11.988 33.494 12.006 33.647 ;
     RECT  8.28 33.485 8.298 33.677 ;
     RECT  0.108 33.647 0.126 33.683 ;
     RECT  11.196 33.494 11.214 33.683 ;
     RECT  10.224 33.377 10.242 33.773 ;
    LAYER M4 ;
     RECT  0.06 3.792 0.097 33.768 ;
     RECT  0.097 3.696 1.969 33.768 ;
     RECT  1.969 3.648 2.293 33.768 ;
     RECT  2.293 2.832 2.408 33.768 ;
     RECT  2.408 2.148 2.653 33.768 ;
     RECT  2.653 1.92 3.251 33.768 ;
     RECT  3.251 1.92 4.669 2.616 ;
     RECT  3.251 3.648 4.669 33.768 ;
     RECT  4.669 1.92 9.173 33.768 ;
     RECT  9.173 33.744 10.253 33.768 ;
     RECT  9.173 1.92 10.289 32.568 ;
     RECT  10.289 1.92 10.865 32.52 ;
     RECT  10.865 1.92 11.441 32.088 ;
     RECT  11.441 1.92 12.121 29.784 ;
     RECT  12.121 1.824 12.901 29.784 ;
     RECT  12.901 1.776 13.045 29.784 ;
     RECT  13.045 1.728 13.208 29.784 ;
     RECT  11.441 30.912 13.208 32.088 ;
     RECT  13.208 1.728 13.312 32.412 ;
     RECT  13.312 1.728 13.504 32.142 ;
     RECT  13.504 1.728 15.073 28.776 ;
     RECT  13.504 29.76 15.073 29.784 ;
     RECT  15.073 1.728 15.493 29.784 ;
     RECT  13.504 30.912 15.493 31.8 ;
     RECT  15.493 1.728 15.908 31.8 ;
     RECT  15.908 1.728 16.012 32.412 ;
     RECT  16.012 1.728 16.204 32.142 ;
     RECT  16.204 1.728 16.373 31.8 ;
     RECT  16.373 1.728 16.453 31.368 ;
     RECT  16.453 1.584 16.501 31.368 ;
     RECT  16.501 1.296 16.693 31.368 ;
     RECT  16.693 0.72 17.797 31.368 ;
     RECT  17.797 0.72 18.085 31.464 ;
     RECT  18.085 0.72 18.608 31.704 ;
     RECT  18.608 0.72 18.712 32.412 ;
     RECT  18.712 0.72 18.904 32.142 ;
     RECT  18.904 0.72 19.331 31.944 ;
     RECT  19.331 31.92 19.379 31.944 ;
     RECT  19.331 0.72 19.667 30.936 ;
     RECT  19.667 0.72 21.564 30.696 ;
     RECT  21.564 24.384 21.593 24.408 ;
    LAYER M5 ;
     RECT  16.512 1.285 16.536 1.573 ;
     RECT  12.816 0.016 12.936 1.717 ;
     RECT  18.48 0.997 18.504 1.765 ;
     RECT  16.464 1.573 16.536 1.813 ;
     RECT  16.464 1.813 16.584 1.861 ;
     RECT  17.616 1.765 18.504 1.861 ;
     RECT  12.816 1.717 13.08 2.137 ;
     RECT  16.464 1.861 18.504 2.137 ;
     RECT  2.4 2.137 2.52 2.151 ;
     RECT  5.1 2.137 5.22 2.151 ;
     RECT  7.8 2.137 7.92 2.151 ;
     RECT  10.5 2.137 10.62 2.151 ;
     RECT  12.816 2.137 13.32 2.151 ;
     RECT  15.9 2.137 18.72 2.151 ;
     RECT  14.688 1.909 14.712 2.197 ;
     RECT  15.9 2.151 18.912 2.197 ;
     RECT  10.5 2.151 10.812 2.533 ;
     RECT  12.816 2.151 13.512 2.581 ;
     RECT  12.816 2.581 13.608 2.629 ;
     RECT  9.648 2.533 10.812 2.677 ;
     RECT  14.688 2.197 18.912 2.677 ;
     RECT  14.688 2.677 19.176 2.725 ;
     RECT  2.4 2.151 2.712 2.821 ;
     RECT  12.624 2.629 13.608 3.061 ;
     RECT  9.264 2.677 10.812 3.157 ;
     RECT  2.304 2.821 2.712 3.205 ;
     RECT  3.936 2.245 3.96 3.205 ;
     RECT  12.528 3.061 13.608 3.301 ;
     RECT  7.8 2.151 8.112 3.397 ;
     RECT  9.264 3.157 11.352 3.397 ;
     RECT  12.528 3.301 13.656 3.635 ;
     RECT  7.8 3.397 11.352 3.829 ;
     RECT  12.528 3.635 13.608 3.829 ;
     RECT  2.304 3.205 3.96 4.163 ;
     RECT  7.8 3.829 13.608 4.211 ;
     RECT  1.152 4.693 1.176 4.741 ;
     RECT  21.408 3.445 21.432 5.027 ;
     RECT  1.152 4.741 1.272 5.075 ;
     RECT  9.12 4.211 13.608 5.363 ;
     RECT  14.688 2.725 19.848 5.411 ;
     RECT  2.304 4.163 3.24 5.461 ;
     RECT  5.1 2.151 5.412 5.509 ;
     RECT  2.304 5.461 3.432 5.603 ;
     RECT  2.4 5.603 3.432 5.651 ;
     RECT  4.704 5.509 5.412 5.651 ;
     RECT  9.264 5.363 13.608 5.989 ;
     RECT  9.264 5.989 13.656 6.325 ;
     RECT  9.12 6.325 13.656 6.659 ;
     RECT  9.168 6.659 13.656 6.755 ;
     RECT  5.1 5.651 5.412 7.093 ;
     RECT  9.168 6.755 13.512 7.139 ;
     RECT  0.144 6.997 0.168 7.187 ;
     RECT  7.8 4.211 8.112 7.285 ;
     RECT  7.632 7.285 8.112 7.475 ;
     RECT  0.192 7.717 0.216 7.907 ;
     RECT  14.784 5.411 19.848 7.957 ;
     RECT  7.8 7.475 8.112 8.245 ;
     RECT  9.264 7.139 13.512 8.245 ;
     RECT  1.152 7.957 1.176 8.291 ;
     RECT  2.4 5.651 2.712 8.293 ;
     RECT  2.4 8.293 2.808 8.485 ;
     RECT  4.992 7.093 5.412 9.013 ;
     RECT  0.192 9.349 0.216 9.539 ;
     RECT  7.8 8.245 13.512 9.541 ;
     RECT  4.992 9.013 5.688 9.589 ;
     RECT  7.8 9.541 13.656 9.925 ;
     RECT  14.64 7.957 19.848 9.925 ;
     RECT  21.408 9.877 21.432 10.163 ;
     RECT  2.4 8.485 3.576 10.933 ;
     RECT  4.752 9.589 5.688 10.933 ;
     RECT  0.144 10.933 0.168 11.219 ;
     RECT  1.152 11.221 1.176 11.363 ;
     RECT  2.4 10.933 5.688 11.459 ;
     RECT  2.4 11.459 5.544 11.555 ;
     RECT  21.408 11.509 21.432 11.699 ;
     RECT  2.4 11.555 3.576 11.749 ;
     RECT  2.304 11.749 3.576 11.891 ;
     RECT  7.8 9.925 19.848 12.229 ;
     RECT  0.144 12.517 0.168 12.803 ;
     RECT  2.4 11.891 3.576 13.045 ;
     RECT  4.752 11.555 5.544 13.045 ;
     RECT  7.8 12.229 20.52 13.331 ;
     RECT  7.8 13.331 20.376 13.523 ;
     RECT  7.8 13.523 19.992 13.573 ;
     RECT  7.68 13.573 19.992 13.619 ;
     RECT  7.68 13.619 19.848 16.021 ;
     RECT  7.536 16.021 19.848 16.213 ;
     RECT  7.536 16.213 20.088 16.885 ;
     RECT  7.536 16.885 20.232 16.933 ;
     RECT  2.4 13.045 5.544 17.125 ;
     RECT  0.144 16.837 0.168 17.459 ;
     RECT  7.536 16.933 20.52 17.797 ;
     RECT  2.4 17.125 6.264 18.851 ;
     RECT  0.144 19.045 0.168 19.331 ;
     RECT  7.536 17.797 21.48 19.571 ;
     RECT  7.536 19.571 21.384 20.003 ;
     RECT  2.4 18.851 5.412 20.053 ;
     RECT  7.536 20.003 21.336 20.099 ;
     RECT  2.4 20.053 6.264 20.387 ;
     RECT  7.536 20.099 21.24 20.389 ;
     RECT  6.768 20.389 21.24 20.531 ;
     RECT  7.536 20.531 21.24 21.155 ;
     RECT  2.4 20.387 5.544 21.443 ;
     RECT  7.68 21.155 21.24 21.779 ;
     RECT  0.144 21.733 0.168 21.923 ;
     RECT  7.68 21.779 20.568 22.261 ;
     RECT  6.912 22.261 20.568 22.355 ;
     RECT  2.4 21.443 5.412 23.411 ;
     RECT  6.912 22.355 20.52 23.797 ;
     RECT  6.912 23.797 20.616 24.805 ;
     RECT  6.912 24.805 21.432 24.851 ;
     RECT  2.4 23.411 2.712 25.045 ;
     RECT  3.888 23.411 5.412 25.045 ;
     RECT  9.36 24.851 21.432 25.235 ;
     RECT  21.408 25.235 21.432 25.331 ;
     RECT  2.4 25.045 5.412 25.571 ;
     RECT  3.888 25.571 5.412 25.573 ;
     RECT  9.36 25.235 20.232 25.859 ;
     RECT  3.888 25.573 5.736 26.149 ;
     RECT  0.144 25.285 0.168 26.243 ;
     RECT  9.36 25.859 19.848 26.291 ;
     RECT  6.912 24.851 8.112 26.293 ;
     RECT  9.36 26.291 11.256 26.293 ;
     RECT  6.912 26.293 11.256 26.531 ;
     RECT  12.864 26.291 19.848 26.675 ;
     RECT  6.912 26.531 8.112 26.819 ;
     RECT  7.008 26.819 8.112 27.011 ;
     RECT  9.36 26.531 11.256 27.155 ;
     RECT  10.224 27.155 11.256 27.203 ;
     RECT  2.4 25.571 2.712 27.253 ;
     RECT  10.224 27.203 11.16 27.539 ;
     RECT  10.32 27.539 11.16 27.635 ;
     RECT  13.2 26.675 19.848 28.117 ;
     RECT  13.104 28.117 19.848 28.259 ;
     RECT  13.2 28.259 19.848 28.547 ;
     RECT  15.024 28.547 19.848 28.739 ;
     RECT  3.888 26.149 5.784 28.837 ;
     RECT  15.504 28.739 19.848 29.219 ;
     RECT  15.504 29.219 19.656 30.275 ;
     RECT  10.32 27.635 10.812 30.371 ;
     RECT  3.888 28.837 6.36 30.419 ;
     RECT  2.4 27.253 2.808 30.515 ;
     RECT  1.152 30.421 1.176 30.611 ;
     RECT  0.144 29.797 0.168 30.659 ;
     RECT  5.1 30.419 6.36 30.659 ;
     RECT  15.9 30.275 19.656 30.947 ;
     RECT  6.72 30.853 6.744 31.043 ;
     RECT  3.888 30.419 3.912 31.379 ;
     RECT  15.9 30.947 19.368 31.379 ;
     RECT  7.8 27.011 8.112 31.429 ;
     RECT  17.808 31.379 19.368 31.475 ;
     RECT  6.864 31.429 8.112 31.715 ;
     RECT  18.096 31.475 19.368 31.715 ;
     RECT  6.96 31.715 8.112 31.763 ;
     RECT  18.6 31.715 19.368 31.955 ;
     RECT  2.4 30.515 2.712 32.409 ;
     RECT  5.1 30.659 5.412 32.409 ;
     RECT  7.8 31.763 8.112 32.409 ;
     RECT  10.5 30.371 10.812 32.409 ;
     RECT  13.2 28.547 13.512 32.409 ;
     RECT  15.9 31.379 16.212 32.409 ;
     RECT  18.6 31.955 18.912 32.409 ;
     RECT  2.4 32.409 2.52 32.423 ;
     RECT  5.1 32.409 5.22 32.423 ;
     RECT  7.8 32.409 7.92 32.423 ;
     RECT  10.5 32.409 10.62 32.423 ;
     RECT  13.2 32.409 13.32 32.423 ;
     RECT  15.9 32.409 16.02 32.423 ;
     RECT  18.6 32.409 18.72 32.423 ;
  END
END hbfd_rly_304_EW_rfc
END LIBRARY
